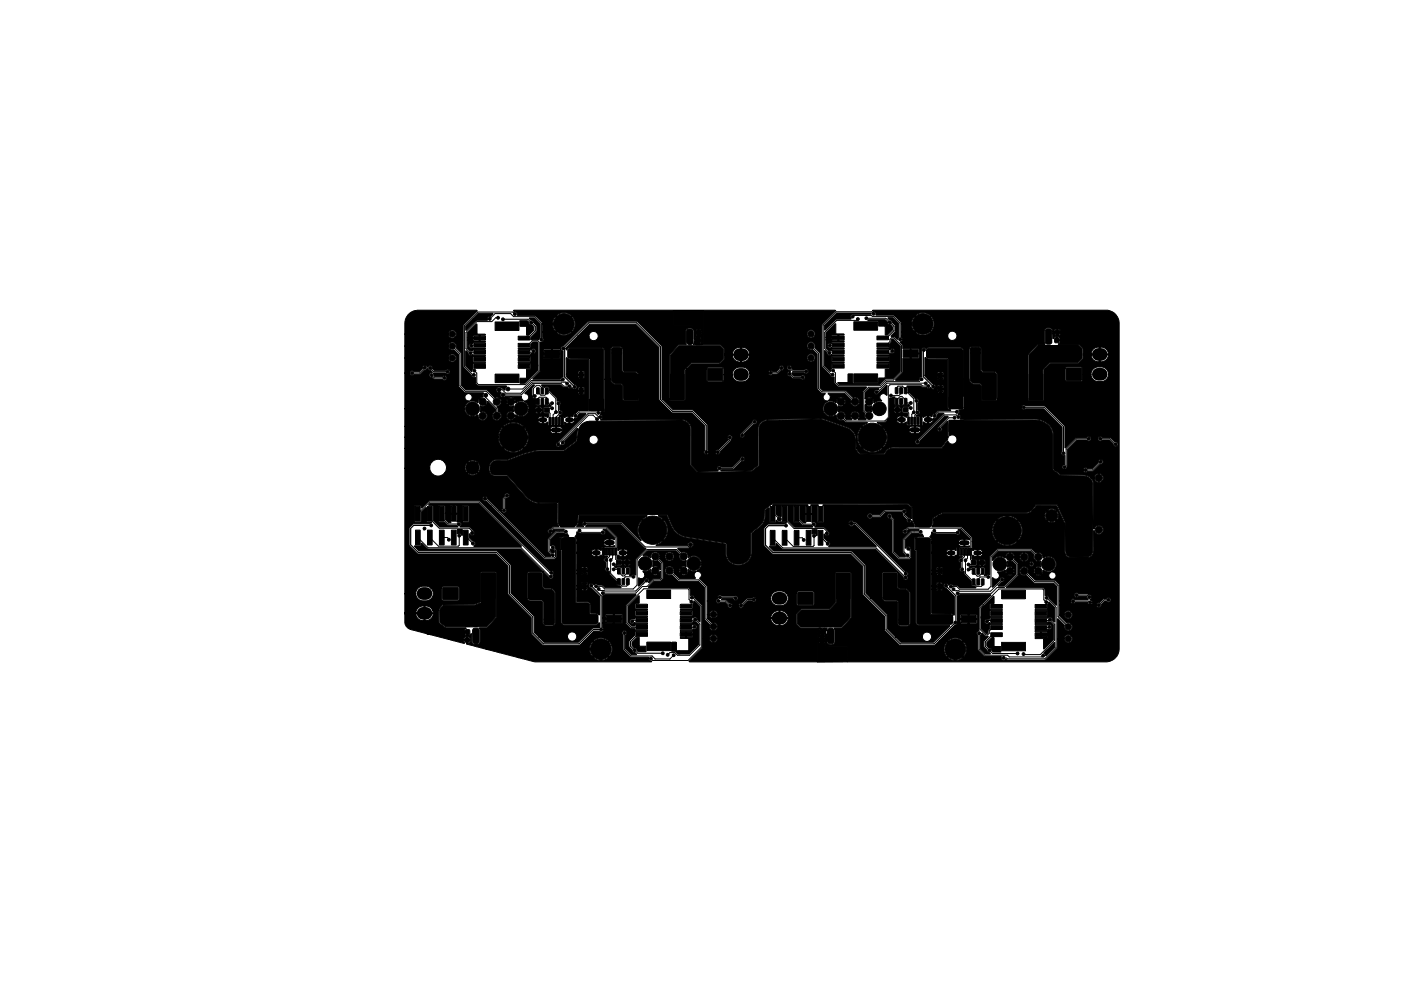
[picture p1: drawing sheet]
<svg xmlns="http://www.w3.org/2000/svg" width="297mm" height="210mm" viewBox="0 0 297 210" stroke-linecap="round" stroke-linejoin="round" font-family="sans-serif">
<g fill="#000" stroke="#000" stroke-width=".21">
<path d="M98.7 74.5l.2-.1 .4 .5a.5 .5 0 0 0 .5 .5l.4-.2 .3 .1 2.4 .1-.1 .2-2.4 .1-.1 1 .2 .1h2.3l.1 .3-2.5 .1-.1 1-.2 .6h-.2l-1.2-1.2zM100.5 77.3h2.4v.8h-2.4zM100.5 75.8h2.4v.8h-2.4zM100.5 74.3h2.4v.8h-2.4zM100.5 72.8h2.4v.8h-2.4zM100.5 71.3h2.4v.8h-2.4zM101 68.7l.1 .1v2.1l1.8 .1v.1h-1.1v1.2h1l.1 .2-2.4 .1-.4 .3a.51 .51 0 0 0-.7 .5 .58 .58 0 0 0 .9 .4h2.5l.1 .2-2.4 .1-.2 .3-.3 .1-.4-.1-.5-.6v-1.6l2.5 .1v-.5h-1.3v.4h-1.2v-.6h2.5v-.5h-1.2l-.1 .5h-1.2v-1zM86.7 66.6l.7-.5 1.2-.3h12.5v.2l-2.9 2.9v9l1.9 2 .7 .1v1.3l.5 .5 6.1 .1-.3 .9-.7-.5a.62 .62 0 0 0-.9-.2 .62 .62 0 0 0-.2 .8 .62 .62 0 0 0 .8 .3l.1 .1a.63 .63 0 0 0 0 .9 .63 .63 0 0 0 1-.1h3.3l.2 .6 .3 .3-.1 .1h-.9l-.6 .4-.3-.9-1.4 1.4a.98 .98 0 0 0 1.1 .1l.1 1.3-.7-.1-.7 .4a.96 .96 0 0 0 .6 1.5h5.9l.4 .5 .6 .1v-.6h-6.6l.6-.2h6v-.7l-.6 .1-.4 .6h-5l.4-1a1.67 1.67 0 0 0 2.6-.7h1.5l.4 .4h.7l.3-.4v-.2h-.6v.6h-.2v-.6h-.6v.2h-1.5l.1-.4h2.8v-.4l-.3-.2h-.3v.6h-.2v-.6l-.5 .1-.1 .5h-1.4a1.78 1.78 0 0 0-.9-1.8l.2-.1a.76 .76 0 0 0 .7-.4 .76 .76 0 0 0-.2-.8l-.6-.3v-.1l1.7-1.7h.3l-.5 .7v1.4l.2 .6 .5 .2 .1 1.3 .3 .2 .6-.2 .4 .2 .1-1 .1 1 .4-.2 .3 .2 .5-.1a.25 .25 0 0 1 .4-.1 .25 .25 0 0 1-.1 .4h-1l-.4 .3v.8l.4 .3h.6l.1 .6-.2 .3-.4-.2-.5-.1v1.5h.4l.5-.2 .2 .7h3.2l.1-.2 .1-.5 .6 .2h.8l.4-.1 .3-.3v-.2h-1v.6h-.2v-1.5h-.4l-.5 .3-.4-.2v1.9h-.2v-1.9l-.6-.1 .3-.2a.54 .54 0 0 0 .5-.7 .54 .54 0 0 0-.6-.4v-.9l.1-.2a.56 .56 0 0 0 0-.7 .56 .56 0 0 0-.7-.1v-.7l-.9-.9h5.4l.1 .2h1l.2-.1v-.6h-.6v.7h-.2v-.7h-.5v.5h-5.4l-.7-.7h7.4l-.1-.6-.5-.1v.7h-.2v-.7l-.5 .1v.6h-6.1l-.2-.7-.9 .1-.3-.2-.2-.3 3.9-.1 .6 .6h.9l.4 .3 .6-.3 .2 .3a.51 .51 0 0 0 .8-.2 .51 .51 0 0 0-.5-.7l-1.5-1.5h2.3l.1 .2h1l.2-.1v-.6h-.6v.7h-.2v-.7h-.5v.5h-2.3l-.3-.3v-.4h3.9v-.5l-.6-.2v.7h-.2v-.7l-.5 .1v.6h-2.6l.1-3.5 .8 .3 3.9 .1v10.8h-2.1l-.6 .6-.4 .1-.3 .6-.6-.1v.7h1v-.3l.5-.1 .2-.5 .5-.4 1.2 .1-6.3 6.4a.5 .5 0 0 0 .2 .5 .5 .5 0 0 0 .5 .1l.4-.4a.52 .52 0 0 0 .7-.2 .52 .52 0 0 0 0-.6l2.6-2.7h.2l-.4 2.6-2.6 2h-5.2l-1.1 .1-2.2 .6-3.4 1.3-2.9 .1-.7 .5-.3 1 .1 1.1 .4 .6 .7 .2h2.6l3.9 4.4 1.1 .9 1.6 .5h4v3.9l.4 1-1.3 .1-.4 .4-.5 .1-.2 .4a.5 .5 0 0 0 .6 .5l.4-.2 .1-.4 .3-.3h2.1l-.1 .2h-1.6l-1.7 1.7v2.8l.5 .6v.4l-1 .1-9.9-9.8h.5a.5 .5 0 0 0 .7 .5 .5 .5 0 0 0 .2-.8l-.1-2.1 .3-.3a.52 .52 0 0 0 .6-.5 .52 .52 0 0 0-.6-.5 .52 .52 0 0 0-.4 .7l-.4 .4v2.1l-.3 .5h-.5l-2.5-2.5a.51 .51 0 0 0-.6-.4 .51 .51 0 0 0-.4 .6 .51 .51 0 0 0 .8 .3l12.2 12.3h2.2l.5-.3v-1.6l-.3-.6a.5 .5 0 0 0-.3-.4 .5 .5 0 0 0-.5 .1l-.2-.1v-1.2l1.4-1.4h1.4l.4 .2 .4-.1 .2 .6-1 .1-.8 .1-.1 .2v2.4l.3 .3 .1 15.4 .6 .3h6.6l.4-.1 .4-.4 .1 .1v1l-1.5 .1-3 3h-7.2l-1.2-1.2h6.1a.98 .98 0 0 0 1.5 .8 .98 .98 0 0 0 .1-1.7 .98 .98 0 0 0-1.6 .7v.2h-6.1l-.9-.9v-3.4l-5-5v-6l-2.9-2.9h-16.6l-.9-1 1.3-.1 .2-.5 1.4 1.2h19.6l4.7 4.8-.1 .1-3-.1-.2 .2v5.3l.1 .4 .4 .3h2.5l.3 .3v4.4l.2 .4 .5 .2h1.4l.5-.5v-6.5l-.1-.3-.6-.6-1.4-.1-.5-.4v-3.1l1.2 1.1 .1 .3a.5 .5 0 0 0 .7 0 .5 .5 0 0 0 .1-.6v-.2a.54 .54 0 0 0 .1-.7 .54 .54 0 0 0-.7-.1l-14.9-14.9h-10.6l-1.7 1.6-.2-.6h-1.1l-.2 .1v3.4h1.3l.1-2 1-1 .1 .1v2.9l1.1 .2-.5 .2h-3.3l-.9 .8v3.9l1.8 1.7h16.5l2.6 2.6v6l4.9 4.9 .1 3.5 2.3 2.4h7.8l1.1-.9h1.9l1.6 1.6 1.6-1.6a2.35 2.35 0 0 0-3.2 0h-1.9l2-2.1 1.2 .1a.5 .5 0 0 0 .8-.3l-.1-1.6h.5l.2 .2h3.3l.1-.1v-.8h-1.7v.9h-.2v-.9h-1.6l-.1 .7h-.5v-.9h4.1v-.7l-.1-.2h-1.6v.9h-.2v-.9h-1.5l-.1 .1-.1 .8h-.5v-4.8l.5-.3h6.4l.1 .2-2.2 2.1v3.8l1.1 1.1 .9 .1 .2 .3 2.5 .1-.1 .2h-2.4l-.2 .7-1.2 1.3v1.2l.8 1.1 .7 .4v.2h-1.1l-1.2-1.3v-2.8l.2-.2a.5 .5 0 0 0-.1-.7 .5 .5 0 0 0-.7 .1 .5 .5 0 0 0 0 .7l.1 3.2 1.5 1.5h3.8l.2 .6 .6 .4h-24.8l-3.6-.9h16a2.37 2.37 0 0 0 3.2 0l-1.6-1.6-1.6 1.6h-16l-6.7-1.8h21.9l.2 .9 .4 .8 1.6-1.7h.3l1.7 1.7a2.35 2.35 0 0 0 0-3.3l-1.7 1.6h-.3l-1.6-1.6-.4 .7-.2 .9h-21.9l-4.2-1.1v-.1l.7-.1 .1-.5h-.6v.6h-.2v-.6h-.6l.2 .5-.1 .1-3.2-.8h4.5v-.4l-.3-.2h-.3v.6h-.2v-.6l-.4 .1-.2 .5h-3.1l-4.7-1.2h8l.2 .3h.3v-.6h-.5v.3h-8l-3.7-1-.6-.5-.3-.6-.1-2.2h2.4a1.56 1.56 0 0 0 1.7 1.5h.2a1.53 1.53 0 0 0 1.7-1.5h-1.7v1.5h-.2v-1.5h-4.1v-.2h6l-.1-.6h1.3l.1 2.6 .1 .3 1.3 .9h4.3l-.3 .4v.4h.7v.8h.4l.3-.4 .1 .1v1.5l.2 .5 .5 .2 .8-.1 .3-.6v-2.2l-.1-.6 1.6-.1 1.9-2.1v-9.5l-.3-.2h-2.8l-.2 .2-.1 6.2-1.2 .5-6.6 .1-1 1.1h-1.3l-.8-.7-.8-.1v1.4h-.2v-1.4a1.56 1.56 0 0 0-1.7 1.4h-2.4v-4h2.4a1.56 1.56 0 0 0 1.4 1.5l1.2-.1 .8-.6 .3-.9-.2-.7-.4-.4h2.4v2.3l.2 .3 3.1 .1 .4-.4v-2.4l-.4-.3h-3l-.3 .4h-2.4l-.6-.4h-1.2l-1 .5-.3 1.1h-2.4v-26.7h5.3a1.78 1.78 0 0 0 1.2 1.6 1.78 1.78 0 0 0 1.9-.5h4.9a1.57 1.57 0 0 0 2.1 0l-1-1-1.1 1h-4.9l.3-.5 .2-.7h3.9l.4 1.1 1-1.1h.3l1.1 1.1a1.57 1.57 0 0 0 0-2.1l-1.1 1h-.3l-1-1-.4 1h-3.9l-.1-.6-.4-.6h4.9l1.1 1.1 1-1.1a1.57 1.57 0 0 0-2.1 0h-4.9l-.9-.5a1.77 1.77 0 0 0-2.2 1.8h-5.3v-4.2h20.9a3.2 3.2 0 0 0 4.3 0l-2.2-2.2-2.1 2.2h-20.9v-2.4h19.8a3.1 3.1 0 0 0 .9 2.3l2.2-2.2h.3l2.2 2.2a3.2 3.2 0 0 0 .5-3.7h4.9l.2 .4 .3 .2 1.4 .1 .5-.2 .2-.5h-1.2v.7h-.2v-.7h-6.1l-.1-.2h7.6l-.2-.4-.4-.2h-.6v.6h-.2v-.6l-.8 .1-.4 .5h-5l-.4-.5-2.2 2.2h-.3l-2.2-2.2a3.1 3.1 0 0 0-.9 2.1h-19.8v-2.2h20.9l2.1 2.1 2.2-2.1a3.2 3.2 0 0 0-4.3 0h-20.9v-3.8h12.7a1.72 1.72 0 0 0 1 1.5 1.72 1.72 0 0 0 1.8-.2l.1 .3a.96 .96 0 0 0 1.2 .8 .96 .96 0 0 0 .5-1.4l-.6-.4h-.7v-1.2l.7 .1 .4-.2-1.3-1.4-.3 .8-.9-.3h-.7v-.1a.77 .77 0 0 0 .4-.8 .77 .77 0 0 0-.5-.6l-.2-.1a.76 .76 0 0 0-.8 .6l.2 .7 .7 .3a1.94 1.94 0 0 0-1 1.6h-12.7v-7.6h1.1a.5 .5 0 0 0 .5 .6l.4-.3h1.3l.8-.8 .4-.1 .3-.3 1 .7-.1 .2a.5 .5 0 0 0-.4 .7l.9 .6h1.8l.1 .1a.51 .51 0 0 0 .7-.1 .51 .51 0 0 0-.1-.7 .51 .51 0 0 0-.7 .2h-1.6l-.3-.7 2.5-.1 .2 .1a.51 .51 0 0 0 .7-.1 .51 .51 0 0 0-.1-.7 .51 .51 0 0 0-.8 .2h-2.3l-.4-.4a.55 .55 0 0 0-.4-.6 .55 .55 0 0 0-.7 .3 .55 .55 0 0 0-.6-.4 .55 .55 0 0 0-.4 .7l-.8 .7h-1a.5 .5 0 0 0-.9 0l-.1 .2h-1v-3.1h9.2a.86 .86 0 0 0 1.3 .7 .86 .86 0 0 0 .1-1.4 .86 .86 0 0 0-1.3 .5l-.1 .2h-9.2v-2.6h9.2a.94 .94 0 0 0 1.3 .8l.9 1 .1 6.8 1.3 1.3h3.9l-.1 .9-.7 .3 1.4 1.3 .2-.6h.2l1.5 1.6 .1 .5-.4 .2a.96 .96 0 0 0 0 1.5 .96 .96 0 0 0 1.5-.3 .96 .96 0 0 0-.5-1.4l-.3-1.1a1.05 1.05 0 0 0 .9-.9l1.1-.1 .2 .6 .6-.6-.6-.6-.2 .6h-1.1l-.4-.7h1.8l.6 .6 .6-.6a.93 .93 0 0 0-1.2 0l-2.8-.2-1.7-1.6h-4.4l-1-1v-6.7l-1.1-1.2a.88 .88 0 0 0-.6-1.2 .88 .88 0 0 0-1.1 .8h-9.2v-2.5h9.2l.1 .2a.86 .86 0 0 0 1.3 .5 .86 .86 0 0 0-.1-1.5 .86 .86 0 0 0-1.3 .8h-9.2l.1-2.9zM98.8 69.1l2.6-2.6h3.1v.1l-.7 .6a.5 .5 0 0 0-.5 .6v.2h-2.3l-2.2 2.1zM105 79.4h5v1.8h-5zM105 68.3h5v1.8h-5zM109.9 77.3h2.4v.8h-2.4z"/>
<path d="M109.9 75.8h2.4v.8h-2.4zM109.9 74.3h2.4v.8h-2.4zM109.9 72.8h2.4v.8h-2.4zM109.9 71.3h2.4v.8h-2.4zM110.2 68.1h1.6l.5 .7 .4 .1 .4 .5v.7l-1 1h-.5v-1.9h-1.3zM112.2 67.5h1.1l1.2 1.2v2.9l-.3 .5h-1.7v-.5l1.3-1.3v-1.1l-.9-1.2-.4-.1zM109.9 73.9l2.5-.1 .1-.8 .5-.4 .9-.1 .2 .2v5.8l-2.9 2.8h-.9l-.1-1 1.4-.1v-1.8l.9-.1v-1l-.2-.2h-2.3l-.1-.2 2.5-.1 .1-1-.2-.2h-2.3l-.1-.2 2.4-.1 .3-.3h.6a.51 .51 0 0 0 .4-.8 .51 .51 0 0 0-.9 0l-2.7-.1zM115.4 74.2h3.2v1.6h-3.2zM120.4 74.2h3.2v1.6h-3.2zM122.8 78.9h.9v1.2h-.9zM126.1 78.9h.9v1.2h-.9zM120.6 74.1l.3-.2h6.6l.5 .3v12.4l-.2 .5h-2.4l-.3-.4v-10.7h-4.4l-.3-.5z"/>
<path d="M129.8 73.9l.3-.2h1.3l.4 .3 .1 4.6 .4 .4h2.4l.4 .3 .1 5-.3 .4h-2.4l-.2-.4v-2.5l-.6-.5h-1.5l-.5-.6-.1-6.4zM145.9 70.1h.8v.9h-.8zM146 73.5h.8v.9h-.8zM146 71.8h.8v.9h-.8zM145.7 70l.9-.2 .3 .4 .1 2.4-.4 .5h-.7l-.3-.4v-2.4zM147.2 72.6l.5 .5h-.7zM147.7 70.1h.8v.9h-.8zM147.6 73.5h.8v.9h-.8zM147.6 71.8h.8v.9h-.8zM142.7 66l6.4-.1v6.7l-.4 .5h-1.1l-.3-.4 .1-.1 .2 .3h.7l.3-.2v-.2h-.3v.4h-.5v-.4l-.5 .1v-.6h1.3v-.3l-.3-.2v.5h-.5v-.5l-.5 .5v-1.2h.2l.4 .4h.6l.3-.4h-.4v.4h-.5v-.4h-.6v-.5h1.5l-.2-.3-.2-.1v.4h-.5v-.4l-.4 .4h-.2v-.8l-.5-.4h-4.1zM143.9 73.4l8.7-.1 .8 .8v1.9l-1 1h-5.9l-1.4 1.5-.1 6.2-2.8 .1-.1-.1v-9.3zM174.8 74.4h.2l.3 .5a.5 .5 0 0 0 .6 .5l.4-.2 .2 .1h2.4v.3h-2.4l-.2 1 .2 .2h2.4l.1 .3h-2.5l-.2 1.1-.2 .6h-.1l-1.2-1.2z"/>
<path d="M176.5 77.3h2.5v.8h-2.5zM176.5 75.8h2.5v.8h-2.5zM176.5 74.3h2.5v.8h-2.5zM176.5 72.8h2.5v.8h-2.5zM176.5 71.3h2.5v.8h-2.5zM108.9 65.8h68.2v.2l-2.8 2.9v8.9l1.9 2.1 .6 .1 .1 1.3 .8 .8h6l-.8 1.1v3.9l.5 .6a1.21 1.21 0 0 0 .2 1.2l-.1 .2-1.5-.1 .2-1-.1-.3-.4-.4h-.8l-.4 .4a1.14 1.14 0 0 0 .1 1.3h-1.1l-.4-.3 .1-.7-.2-.5-.5-.2-.8 .1 .1-1.3a.96 .96 0 0 0 1.1-.1l-.8-.8h.3l.6 .6a.95 .95 0 0 0 0-1.2l-.6 .6h-.3l-.6-.6-.2 .8-.7-.3-1-.1 .4-.5h1.7l.6 .6 .6-.6a.93 .93 0 0 0-1.2 0h-1.7l-.1-.6-.3-.4 3.4-.1 1.4 1.3-.1 .3a.97 .97 0 0 0 .9 1.2 .97 .97 0 0 0 1-1v-.3l-.4-.5-.3-.1h-.7l-1.5-1.5h-4.9l-.5-.5v-7.4l-1.1-1.1a.89 .89 0 0 0-.7-1.3 .89 .89 0 0 0-1 1 .89 .89 0 0 0 1.3 .7l.9 .9v7.4l.8 .9h.8l.1 .2a.79 .79 0 0 0-.5 .7 .79 .79 0 0 0 .5 .7l.5 .2a1.71 1.71 0 0 0-.8 2.4 1.71 1.71 0 0 0 2.6 .4v.3a.98 .98 0 0 0 1.4 .8l.7 .5h4.5v.2l-1.1 .7 2.2 2.1 2.1-2.1-1-.7v-.2h1.6l.4-.5h2l.3 .6 .7 .1v-.7h-3l.3-.2h2.7v-.6l-.6 .1-.4 .5h-1.7l.2-.3v-1.4h.9l.4 .4h.9l.2-.4v-.1h-.6v.5h-.2v-.5h-.7v.1h-.9v-.4h2.4v-.3l-.4-.2h-.2v.5h-.2v-.5l-.5 .1-.2 .4h-.9v-2.4l1.1-.2-.1 1.5 .2 .3 .8-.1 .3 .1 .1-.9 .2 .9 .3-.1 .7 .1 .2-.1a.24 .24 0 0 1 .4 0 .24 .24 0 0 1-.1 .4h-1.1l-.3 .2v.9l.3 .2h.7l.1 .7-.2 .3-.4-.3h-.5v1.5h.4l.4-.3 .3 .7h3.1l.2-.1 .1-.6 .5 .3h.9l.4-.2 .2-.3 .1-.2h-1v.7h-.2v-1.5h-.5l-.4 .3-.4-.3v1.9h-.2v-1.9l-1-.1 .8-.4a.6 .6 0 0 0-.4-.9v-1.4l.2-.3a.51 .51 0 0 0-.2-.5 .51 .51 0 0 0-.5-.1l-1.5-1.5h6.2l.2 .2h.9l.2-.1v-.6h-.6v.7h-.2v-.7h-.5v.5h-6.2l-.3-1.2h2.8l.4 .2 .9 .1 .4 .2 .6-.2 .3 .3 .2 .1 .3-.2h1.9v-.5l-.6-.2v.7h-.2v-.7h-.4l-.1 .7h-.5a.53 .53 0 0 0-.5-.9l-1.2-1.2h2.2l.2 .2h.9l.2-.1v-.6h-.6v.7h-.2v-.7h-.5v.5h-2.2l-.5-.5v-.2h4v-.5l-.6-.2v.7h-.2v-.7l-.5 .1v.6h-2.7v-3.7l.9 .3h3.9v10l.1 .6 .6 .3h-2.7l-.6 .6-.5 .1-.2 .6-.7-.1v.6h.9l.1-.2 .6-.1 .1-.5 .5-.4h1l-5.5 5.5a.51 .51 0 0 0-.6 .7l.2 .2a.51 .51 0 0 0 .5 .1 .51 .51 0 0 0 .3-.5l5.3-5.4h.7v.2l-2 1.9-.3 .7a.51 .51 0 0 0 .8 .4 .51 .51 0 0 0 .1-.8l1.2-1.3h.2l.1 3.3-.2 .6-1.3 1.6h-10.5l-.8 .3-.9 1h-4.5a1.18 1.18 0 0 1-1.3-1.1h1.2a3.2 3.2 0 0 0 4.3 0l-2.2-2.2-2.1 2.2h-1.2v-1.9h.2l.2 .9 .6 .9 2.2-2.2h.3l2.2 2.2a3.1 3.1 0 0 0 .5-3.7h4.9l.2 .4 .3 .2h1.4l.4-.1 .3-.5h-1.2v.6h-.2v-.6h-6.1l-.2-.2h7.7l-.2-.4-.5-.3h-.5v.7h-.2v-.7l-.8 .1-.4 .6h-5.1l-.3-.5-2.2 2.2h-.3l-2.2-2.2a3.6 3.6 0 0 0-.9 2.5l-.7-1.4-.8-.8-5.6-2-1.1-.1-10.9 .2-1.2 .6-.4 .4-.3 .7v8l-1.4 1.1-6.5 .1 .2-.3h2.5l1.8-1.7a.52 .52 0 0 0 .6-.6 .52 .52 0 0 0-.6-.4 .52 .52 0 0 0-.4 .6l-1.7 1.6h-2.3a.5 .5 0 0 0-.6-.2 .5 .5 0 0 0-.3 .6l.3 .3-.1 .2h-4.2l-1.4-1.4-.1-8-.4-.8-.7-.6-.9-.2-17.1 .2-.1-.2a.58 .58 0 0 0 .5-.5 .58 .58 0 0 0-.5-.6l.1-.5 .7-.1 .1-.2v-6.6h1.2l.1 .4 .6 .6 1.5 .1 .4 .3 .1 2.9 .1 .2h3l.1-.1 .1-.6v-4.9l-.6-.5-2.4-.1-.3-.2v-4.4l-.1-.3-.4-.3h-1.6l-.6 .5v6.4h-1.2v-6.1l-.3-.6-.4-.1h-6.6l-.4 .1-.4 .5-.2-.3 2.5-2.7h2.5a.98 .98 0 0 0 1.4 .9 .98 .98 0 0 0 .1-1.7 .98 .98 0 0 0-1.5 .7v.1h-2.5l2.6-2.5h9.8l4.9 4.9v11.2l2.7 2.7h4.3l2.7 2.7v5.2l-.2 .3a.51 .51 0 0 0 .6 .6l.4-.2v-.3h1.5a.5 .5 0 0 0 .5 .5l.3-.1 .2-.5 2.2-2.2 .3-.8-.2-.4h1.9a.52 .52 0 0 0 .7 .5 .52 .52 0 0 0 .2-.8l2-2.1h.2a.51 .51 0 0 0 .5-.6 .51 .51 0 0 0-.6-.4 .51 .51 0 0 0-.4 .6l-2.4 2.4-.2 .4h-1.9a.56 .56 0 0 0-.7 .2 .56 .56 0 0 0 .1 .7l-2.1 2.1-.4 .1-.2 .4h-1.5l-.1-.4-.1-5.5-3.1-3-4.2-.1-2.3-2.2h1.5l.2 .3 3.1-.1 .1-6.3 .2-.3h4.3v2.3l.3 .4h3l.4-.4v-1.1h1.8v.3a1.57 1.57 0 0 0 1.4 1.2h1l.7-.3 .5-.8v-.8h4a.5 .5 0 0 0 .6 .5l.4-.2h.9l.8-.8 .5-.1 .1-.5h.6a.5 .5 0 0 0 .6 .5l.2 .3-.6 .2-.1 .4 .2 .3 .5 .1 .5 .5h1.6l.2 .2a.5 .5 0 0 0 .8-.3 .5 .5 0 0 0-.6-.6l-.4 .2h-1.4l-.3-.3-.1-.4h2.6l.1 .1a.5 .5 0 0 0 .7-.1 .5 .5 0 0 0 0-.7 .5 .5 0 0 0-.8 .1h-2.2l-.4-.3a.52 .52 0 0 0-.5-.7 .52 .52 0 0 0-.6 .5l-.6-.1a.53 .53 0 0 0-.6-.3 .53 .53 0 0 0-.4 .6l-.6 .6h-.8a.5 .5 0 0 0-.8 0l-.1 .3h-4a1.55 1.55 0 0 0-1.3-1.2h-1l-.7 .3-.5 .6-.1 .7h-1.8v-1.2l-.4-.4h-3l-.3 .4h-4.3l1.1-1.1h5.9l1-1 .1-.8h1.7a1.56 1.56 0 0 0 1.7 1.4h.2a1.53 1.53 0 0 0 1.6-.9h12.3v.2a.86 .86 0 0 0 1.4 .5 .86 .86 0 0 0-.2-1.5 .86 .86 0 0 0-1.2 .8h-12.3l.2-.6h-1.8v1.5h-.2v-1.5l-3.4 .1v-.3h5.4a1.54 1.54 0 0 0-1.5-1.4h-.3v1.4h-.2v-1.4a1.54 1.54 0 0 0-1.7 1.4h-1.7l-.1-1.1-.9-.8-4.2-.1h.3l.4-.5v-1.8h22a.86 .86 0 0 0 1.2 .8 .86 .86 0 0 0 .2-1.4 .86 .86 0 0 0-1.4 .5v.1h-22v-4.9l-6.4 .1v3.1h4.1l.5 .4v2.4l-.3-2-.5-.3-.8 .1-.3 .6v2.3l.1 .5-1.7 .1-1.9 2.1v9.4l-1.5-.1-.1-11.2-5.2-5.2h-10.5l-5.1 5.2-.4 .2-.3 .5h-1.7v.8h1.7l.1-.7 .5 .3v5.4l-.6 .6-5.8-.1 1.6-1.7v-2.8h.6l.2 .1h3.2l.2-.1v-.8l-1.7 .1v.8h-.2v-.9h-1.7v.8h-.6v-1h2.3v-.9l-1.6 .1-.1 .8h-.6v-2.3a.56 .56 0 0 0 .6-.2 .56 .56 0 0 0 0-.6l-.1-.2v-1.1h2.8a2.37 2.37 0 0 0 3.3 0l-1.7-1.6-1.6 1.6h-2.8v-1.8h2l.2 .9 .5 .8 1.6-1.7h.3l1.6 1.7a2.38 2.38 0 0 0 0-3.3l-1.6 1.6h-.3l-1.6-1.6-.5 .7-.2 .9h-2l-.1-.3-1.4-1.4h4.3l1.6 1.6 1.7-1.6a2.35 2.35 0 0 0-3.3 0l-8.3-.2a.61 .61 0 0 0-.6-.8zM175.1 70.6l2-1.9 .1 .1v2l1.8 .1-.1 .2h-1v1.2h1v.3h-2.4l-.3 .3a.51 .51 0 0 0-.8 .4 .58 .58 0 0 0 1 .4l2.5 .1 .1 .2-2.5 .1-.2 .3h-.6l-.6-.6v-1.7l2.5 .2 .1-.5h-1.4v.3h-1.2v-.5h2.5l.1-.5h-1.2l-.2 .1v.4h-1.2zM181 68.3h5.1v1.8h-5.1zM181 79.3h5.1v1.8h-5.1zM174.8 69.1l2.7-2.7h7.1l.1 .1-.1 .2h-4a.6 .6 0 0 0-.1 1h-3.2l-2.4 2.3zM185.9 77.3h2.5v.8h-2.5zM185.9 75.8h2.5v.8h-2.5z"/>
<path d="M185.9 74.3h2.5v.8h-2.5zM185.9 72.8h2.5v.8h-2.5zM185.9 71.3h2.5v.8h-2.5zM184.1 67.9l3.6-.1 .4 .5 .2 .5 .5 .1 .4 .4v.7l-1 1.1h-.5v-1.9h-1.4l-.1-1.1h-2.1zM188.3 67.4h1.1l1.2 1.3v2.8l-.3 .5-.7-.6-.7-.1 .9-1 .1-1.1-.9-1.2-.4-.1zM177.6 81.2l2.2-.1v-1.7l.9-.1 .3 2h5.2l.1-1.1h1.4v-1.8l.8-.2 .1-.9-.2-.2h-2.4l-.1-.3h2.6l.1-1-.2-.2h-2.4l-.1-.3h2.5l.2-.3h.4a.56 .56 0 0 0 .7-.5 .5 .5 0 0 0-.7-.5l-.4 .3-.2-.2h-2.4l-.1-.2 2.6-.1 .1-.9 .3-.3 .1-.5 .2-.2h.2l1.5 1.5v5.4l-1.6 1.6h-1.6l-1.3 1.2h-8.5zM191.5 74.2h3.2v1.6h-3.2zM196.5 74.2h3.2v1.6h-3.2zM199 79.1h.9v1.2h-.9zM202.3 79.1h.9v1.2h-.9zM196.6 74l.4-.1h6.6l.4 .2 .1 12.1-.3 .5h-2.2l-.5-.4v-10.3l-4.4-.1-.2-.4v-1.1zM205.8 73.8l.4-.1h1.2l.5 .3v4.6l.4 .4h2.4l.5 .3v4.9l-.2 .5h-2.4l-.3-.4v-2.5l-.5-.5-1.5-.1-.6-.5v-6.5z"/>
<path d="M221.9 70.1h.9v.8h-.9zM222 73.4h.8v1h-.8zM222 71.7h.8v1h-.8zM221.8 69.9l.8-.1 .4 .3v2.4l-.3 .5h-.7l-.4-.3v-2.4zM223.8 70.1h.8v.8h-.8zM223.7 73.4h.8v1h-.8zM223.7 71.7h.8v1h-.8zM220 73.3h8.6l.8 .8v1.9l-.9 1h-5.9l-1.5 1.5v6.2l-2.8 .1-.1-.2v-9.2zM122.8 109.4h14.3l.1 .1-1 .7 2.2 2.1 2.2-2.1-1-.8h1.7l1.4 2.9 .9 1 .8 .4 1.1 .4 8.4 1.3v2.4l.3 .8 .9 .9 1.2 .4 1-.1 .6-.2 .8-.6 .4-.5 .3-1.3v-4l1.9-1.6 .5-.6 .4-1.1 .1-1.7 .7-.5 .1 .1 .1 3h1.2l.1-.4h.2a.6 .6 0 0 0 .8 .3l.3 .1h.8l.1 .2-.5 .2h-3.3l-.9 .7v4l1.9 1.7h16.5l2.5 2.6v5.9l4.6 4.6 .1 3 3.1 3.2h7.4l1-.9h1.8l1.6 1.6 1.7-1.6a2.38 2.38 0 0 0-3.3 0h-1.8l3.4-3.4 .4-.1 .1-.3h.6l.2 .1h3.2l.2-.1v-.8h-1.7v.9h-.2v-.9h-1.7v.8h-.6v-1h4.2v-.7l-.2-.2h-1.5v.9h-.2v-.9l-1.6 .1-.1 .8h-.6v-4.7l.5-.3h6.6l-2.6 2.7v4.6l.1 .3-.3 .2a.5 .5 0 0 0 0 .7v3.2l1.3 1.3 3.6 .1 .1 .1a.5 .5 0 0 0 .5 .7l.4-.2 .4 .1h8l2.6-2.5v-2h1.4a.86 .86 0 0 0 1.3 .8 .86 .86 0 0 0 .1-1.5 .86 .86 0 0 0-1.4 .5v.2h-1.4v-4.2h.2l1.3 1.3a.88 .88 0 0 0 .5 1.3 .88 .88 0 0 0 1.1-.9 .88 .88 0 0 0-1.1-.8l-1.5-1.5v-.3h.9a.86 .86 0 0 0 1.3 .8 .86 .86 0 0 0 .1-1.4 .86 .86 0 0 0-1.4 .5v.1h-.9v-2h7.8l.2 .4a.5 .5 0 0 0 .8-.3v-.3l.7-.7 .5 .1a.51 .51 0 0 0 .7-.1 .51 .51 0 0 0-.1-.7 .51 .51 0 0 0-.7 .2h-.6l-.9 .8-.4 .2-.2 .4h-7.8v-.9h2.3l.1 .3 .3 .2 .6-.2h2.5l.3 .4a.5 .5 0 0 0 .8-.2 .5 .5 0 0 0-.4-.7l-.1-.1 .2-.1a.53 .53 0 0 0 .1-.7 .53 .53 0 0 0-.6-.3l-.3-.1h-1.8a.51 .51 0 0 0-.9 0 .5 .5 0 0 0 .1 .6 .5 .5 0 0 0 .6 .1l.2-.2h1.6l.4 .7-2.8 .1a.5 .5 0 0 0-.8 0l-.1 .2h-2.3l-.1-3.5-1-.9h-4.1l-1.2-1.2h1.2a.93 .93 0 0 0 1.2 0l-.6-.6-.6 .6h-1.2l-.2-.3v-.4h1.1l.2 .6 .6-.6-.6-.6-.2 .6h-1.1l-.3-.7-.5-.3-.5 .1-.5 .3a.96 .96 0 0 0 .6 1.5h.7l1.7 1.6 4.1 .1 .6 .6v4h-.2l-1.4-1.4a.56 .56 0 0 0-.6-.7h-.2v-1.2l-.4-.4-7.8-.1 2.5-2.6v-2.4h2.3v.2a.5 .5 0 0 0 .7 .3 .51 .51 0 0 0 .1-.9 .51 .51 0 0 0-.8 .4h-2.3l-.9-.9 .1-.5h1.1l.3 .7a.96 .96 0 0 0 1.1 .1 .96 .96 0 0 0 .5-1l-.3-.5-.7-.3-.6 .3-.3 .7h-1.1l-.2-.6-.2-.2-.6-.2-.3 .1a.96 .96 0 0 0-.6 1l-.1 .1-.6-.3-.8-.1-.7 .3-.5 .6-.1-.1v-.6l1.3-1.3h6.8l.8 .8a1.01 1.01 0 0 0 .1 1.1l.5 .3h.8v1.2l-.7-.1-.5 .2 1.4 1.4 .2-.8 .7 .3 1 .1a.79 .79 0 0 0-.4 .8 .79 .79 0 0 0 .6 .7 .77 .77 0 0 0 .9-.8l-.2-.5-.7-.3v-.1a1.66 1.66 0 0 0 .8-2.1 1.66 1.66 0 0 0-2-1l-.7 .3-.1-.6-.3-.4-.6-.2-.4 .1-1.1-.9h-7.1l-1.6 1.6-.1 3.9-1.1 .2 .1-1.5-.2-.3-.7 .2-.4-.2-.1 1-.1-1-.4 .2-.3-.2-.5 .1a.28 .28 0 0 1-.4 .2 .28 .28 0 0 1-.2-.4l.3-.2 1 .1 .4-.4h.2l.4 .4h.8l.3-.4v-.2h-.6v.6h-.2v-.6h-.6l-.1 .2h-.2v-.4h1.7l-.2-.5-.4-.1v.6h-.2v-.6l-.4 .1-.3 .5h-.2l-.2-.5-.9-.2-.1-.5 .2-.3 .6 .3h1l.4-.3 .2-.4h-1v.7h-.2v-.9h1.1v-.1l-.3-.4-.3-.1h-.3v.6h-.2v-.6l-1 .2-.1-1.9h5.3a3.2 3.2 0 0 0 4.3 0l-2.2-2.2-2.1 2.2h-5.3v-.9l-1.4-1.5h5.6l.2 1.1 .7 1.2 2.2-2.2h.3l2.2 2.2a3.2 3.2 0 0 0 .1-4.3h6a1.45 1.45 0 0 0 1.9 0l-.9-.9-1 .9h-6l-.1-.1-2.2 2.2h-.3l-2.2-2.2a3 3 0 0 0-.9 2.1h-5.6l-.9-.7h-6.1l-.1-.1 .2-.6 .1-.8h13.5l2.1 2.1 2.2-2.1a3.2 3.2 0 0 0-4.3 0h-13.5v-.3l1.2-.6h22.4l.4 1 .9-1h.3l1 1a1.46 1.46 0 0 0 0-2l-1 1h-.3l-.9-1-.4 1h-22.4l.8-.5h17.6l.8-.2 .7-.4h3l1 1 .9-1a1.43 1.43 0 0 0-1.9 0h-3l.7-1 4.4 .1 1.6 3.6 .1 6 .2 .7 .4 .5 4.2 .1 .8-.4 .5-.9v-4.3l.1-.1a.96 .96 0 0 0 1.6 .5 .96 .96 0 0 0-.2-1.6 .96 .96 0 0 0-1.4 .7h-.1l-.1-9.6-.2-.7-.3-.5h.7v.2a.96 .96 0 0 0 1.6 .5 .96 .96 0 0 0-.2-1.6 .96 .96 0 0 0-1.4 .9h-.7l-.7-.4-.7-.2-5-.1-1.3-1h6.1l.1 .4 .4 .1 .4-.2h1.1l1.5-1.5h.2a.52 .52 0 0 0 .5-.6 .52 .52 0 0 0-.7-.4 .52 .52 0 0 0-.3 .6l-1.3 1.3h-1a.5 .5 0 0 0-.8 .1l-.1 .2h-6.1l-.2-.2-.1-8-.8-1.3-1.5-1-1.6-.3-15.1 .1h-.7v-.2a.56 .56 0 0 0-.5-.9l.3-.4-.1-.5 1-.1 .1-.5h12.1a.5 .5 0 0 0 .6 .5l.4-.2h3.8l3.9 3.9v5.1l-.2 .2a.5 .5 0 0 0 .4 .8h.4v1.8l-.4 .2a.5 .5 0 0 0-.1 .8h.1a.52 .52 0 0 0 .6 .1 .52 .52 0 0 0 .2-.6l.1-3.6 2.1-2.1h2l.1 .2a.51 .51 0 0 0 .6 0 .51 .51 0 0 0 .2-.4h1.5a.51 .51 0 0 0 .7 .4l.3-.2 1.4 .1 .8 .7 .2 .6a.52 .52 0 0 0 .8-.4 .52 .52 0 0 0-.6-.6l-1-.9h-1.7a.51 .51 0 0 0-.8 0l-.1 .3h-1.5v-.2a.55 .55 0 0 0-.9-.1h-2.2l-2.4 2.3-.1-4.8-4.2-4.2h-4.1a.5 .5 0 0 0-.8 0l-.1 .3h-12.1l-.1-6h1.2l.1 .4 .6 .6 1.5 .1 .4 .3v3l.1 .1 3 .1 .2-.4h6.6l.2 .4h2.8l.3-.1v-.3v-6l.3-.4h4.2v2.4l.4 .4h3l.3-.4v-1.1h1.8a1.55 1.55 0 0 0 1.5 1.5l.9-.1 .7-.3 .6-.8v-.7a1.57 1.57 0 0 0-1.4-1.2h-1l-.7 .3-.4 .5-.2 .8h-1.8v-1.3l-.4-.3h-2.9l-.4 .3h-4.2l1.1-1h5.8l1.1-1v-.9h1.7a1.56 1.56 0 0 0 1.8 1.5l.2-.1a1.52 1.52 0 0 0 1.7-1.4h-1.7v1.4h-.2v-1.4h-3.5v-.2h5.4a1.54 1.54 0 0 0-1.4-1.4h-.3v1.4h-.2v-1.4a1.54 1.54 0 0 0-1.8 1.4h-1.7v-1.1l-.9-.9h-4.3l.3-.4v-.4h-.6l-.1-.2h.7v-.4l-.5-.2v.6h-.2v-.6h-.4l-.4 .3v-1h.3l.3 .4h.7l.3-.2 .1-.4h-.6v.6h-.2v-.6h-.6v.2h-.3v-.4h1.7l-.2-.4-.4-.2v.6h-.2v-.6h-.3l-.3 .3v.3h-.3l-.1-.4-.2-.3-1.1-.1-.4 .7v2.2l.2 .6-1.7 .1-1.9 2.1v9.3h-6.6v-5.3l-.5-.5h-2.5l-.2-.3-.1-4.3-.3-.6-1.8-.1-.5 .5v6.4h-1.2v-6l-.3-.6-.4-.1h-6.6l-.7 .3a.51 .51 0 0 0-.6-.2 .51 .51 0 0 0-.3 .6v5.5l-.4 .3-.1 .4-5 .1v-.2l1.5-1.5v-3h3.3l.2-.2v-.7h-1.7v.9h-.2v-1.1h1.9l-.1-.8-1.6-.1v.9h-.2v-.9h-1.6v-.8l-.5-.6a.59 .59 0 0 0 .4-.4 .59 .59 0 0 0-.2-.6v-.3h9.8l.2 .6 .3 .2a.98 .98 0 0 0 1.2-.1 .98 .98 0 0 0 .2-1.2l-.4-.4a.98 .98 0 0 0-1.5 .9h-9.8v-.8h2.9a2.37 2.37 0 0 0 3.3 0l-1.7-1.6-1.6 1.6h-2.9v-1.8h2.1l.2 .9 .5 .8 1.6-1.7h.3l1.6 1.7a2.35 2.35 0 0 0 0-3.3l-1.6 1.6h-.3l-1.6-1.6-.5 .7-.2 .9h-2.1l-.1-.4-1.3-1.3h4.3l1.6 1.6 1.7-1.6a2.35 2.35 0 0 0-3.3 0l-8.2-.1-.1-.2a.51 .51 0 0 0-.5-.6l-.2-.1v-.2h49.5a2.79 2.79 0 0 1 2.8 2.8l-.1 69.7a2.78 2.78 0 0 1-2.7 2.1h-54.9v-.9h21.3a2.37 2.37 0 0 0 3.3 0l-1.7-1.6-1.6 1.6h-21.3v-1.8h20.5l.2 .9 .5 .8 1.6-1.7h.3l1.6 1.7a2.38 2.38 0 0 0 0-3.3l-1.6 1.6h-.3l-1.6-1.6-.5 .7-.2 .9h-20.5v-.5h-4l-.5-.3v-2.4l.3 2 .5 .3 .8-.1 .3-.6v-2.3l-.1-.5 1.7-.1 1.9-2.2v-9.3l-.1-.2-.3-.1h-2.8l-.2 .1v6.3l-1.3 1.4h-5.9l-1.1 1v2.1l.8 .9 4.4 .1h-.3l-.4 .4v6.7h-27.2v-.1l2.8-2.9 .1-1.9h1.4a.86 .86 0 0 0 1.2 .7 .86 .86 0 0 0 .2-1.4 .86 .86 0 0 0-1.4 .5v.2h-1.4l-.1-7-1.7-1.8a.53 .53 0 0 0-.7-.4h-.1l-.1-1.3-.4-.4h-8.4l1.2-1.3h1.4l.5-.5v-3.3l-.8-1 .1-.5h1.1l.1 .6 .4 .3a.96 .96 0 0 0 1.4-.8l-.3-.7-.7-.3-.6 .3-.3 .6h-1.1l-.3-.6-.7-.3-.6 .3-.4 .9-.6-.3-1-.2 1-1h6l.8 .8-.1 .6 .2 .5 .5 .3 .8-.1-.1 1.3a.96 .96 0 0 0-1.1 .1l1.4 1.4 .3-.9 .6 .3 1 .2a.99 .99 0 0 0-.2 1.4h-3.3l-1-.9h1.2a.93 .93 0 0 0 1.2 0l-.6-.6-.6 .6h-1.2l-.2-.3v-.4h1.1l.2 .6 .6-.6-.6-.6-.2 .6h-1.1l-.3-.7-.5-.3-.5 .1-.5 .3a.96 .96 0 0 0 .1 1.2 .96 .96 0 0 0 1.1 .3l1.5 1.3h4.2l1.3 1.3 .1 6.8 1 1.1a.89 .89 0 0 0 .7 1.3 .89 .89 0 0 0 1-1 .89 .89 0 0 0-1.2-.7l-.9-.8h13.4a1.56 1.56 0 0 0 1.8 1.4h.2a1.52 1.52 0 0 0 1.7-1.5h-1.7v1.5h-.2v-1.5l-15.2 .1v-.9h.4v.2a.86 .86 0 0 0 1.4 .4h15.3a1.51 1.51 0 0 0-1.4-1.4h-.3v1.4h-.2v-1.4a1.56 1.56 0 0 0-1.8 1.4h-11.6a.86 .86 0 0 0-.2-1.4 .86 .86 0 0 0-1.2 .8h-.4v-2.9h1.8a.5 .5 0 0 0 .5 .5l.4-.2h1l.6 .5v.3a.5 .5 0 0 0 .7 .4l.3-.5h1.3l.2 .4a.51 .51 0 0 0 .5 .1 .51 .51 0 0 0 .3-.5l.9-1 1 .1a.5 .5 0 0 0 .8-.2v-.4h3.1a1.56 1.56 0 0 0 1.5 1.5l1.2-.1 .7-.6 .3-.9-.2-.7-.3-.4h2.3v2.3l.3 .3h3.2l.2-.3v-2.5l-.4-.2h-2.9l-.4 .4h-2.3l-.6-.4h-1.3l-.9 .5-.3 .6-.1 .5h-3.1a.55 .55 0 0 0-1-.1h-1l-1 1.1-.5 .1-.2 .4h-1.3a.53 .53 0 0 0-.6-.5l-.8-.7-.8-.1-.1-.1 2.4-.1 .2 .3a.51 .51 0 0 0 .9-.3 .51 .51 0 0 0-.7-.5l-2.8-.1a.5 .5 0 0 0-.8 .1l-.1 .5-.3 .5h-1.8l-.1-3.1-1.6-1.7a.78 .78 0 0 0-.1-1.4l-.4-.2a1.82 1.82 0 0 0 1-1.5l-.1-.2a1.72 1.72 0 0 0-2.8-1.1l-.3-.9-.5-.3-.6 .1-.8-.8 .1-.1h2.1l.3-.1a.63 .63 0 0 0 .8-.4 .63 .63 0 0 0-.5-.8 .63 .63 0 0 0-.7 .7l-.1 .1h-6.6v-.2l.9-.4 .6-.4-2.3-2.3h.2l2.2 2.2a3.1 3.1 0 0 0 0-4.4l-2.2 2.2h-.2l-2.2-2.2a3.3 3.3 0 0 0-.2 4.3l-.1 .1-3.9-3.9h-7.5l-.5-.2-.4 .4 .2 .7h-1.4l.3-.7zM113.8 84.6h.5l-.1 1.3-.4-.1zM113.8 82.3l.5 .1-.1 1.2-.4-.1zM113.7 86.6h1v.8h-1z"/>
<path d="M114.7 84.6h.6l-.1 1.3-.5-.1zM114.7 82.3l.6 .1-.1 1.2-.5-.1zM115.7 84.6h.5l-.1 1.3-.4-.1zM115.7 82.3l.5 .1-.1 1.2-.4-.1zM116.4 88.6h.4v1.5h-.4zM115.5 86.6h.9v.8h-.9zM117 88.6h.5v1.5h-.5zM117.7 88.6h.4v1.5h-.4zM118.3 88.6h.5v1.5h-.5zM119 88.6h.4v1.5h-.4zM122.8 82.3h.9v1.2h-.9zM126.1 82.3h.9v1.2h-.9z"/>
<path d="M125 89.6h3v2.4h-3zM125 84.7h3v2.4h-3zM132.3 79.4h2.9v5.4h-2.9zM142.2 79.4h2.9v5.4h-2.9zM150 78.2h3.2v2.5h-3.2zM104.4 98.1l.6-.3 2.6-.1 3.5-1.3 2.5-.7h6l2.7-2.1 .1-.3h2.5v.3a.98 .98 0 0 0 1.6 .4 .98 .98 0 0 0-.3-1.6 .98 .98 0 0 0-1.3 .9h-2.5l.1-1.4a2.54 2.54 0 0 1 1.6-2.3l.9-.2 19.5-.2a1.79 1.79 0 0 1 1.8 1.8v7.7l1.5 1.6 11.6-.3 1.5-1.2v-7.8a1.97 1.97 0 0 1 2.1-1.8l10.9-.2 1 .2 4.6 1.6a2.81 2.81 0 0 1 1.9 2.6v1.9l.8 1.1h5.3l.9-1 .7-.3h10.6l1.2-1.6 .1 .2a.99 .99 0 0 0 1.4 .4 .99 .99 0 0 0 .3-1.4 .99 .99 0 0 0-1.4-.2l-.1-2.5 .2-.6 .3-.2 17.7-.1a4.1 4.1 0 0 1 2.5 .8l.2 .2a2.76 2.76 0 0 1 1 2.2v7.3l1.7 1.3 4.8 .1a1.76 1.76 0 0 1 2 1.6l.1 14.1a1.22 1.22 0 0 1-1.1 1.4h-3.8a.97 .97 0 0 1-.8-1.1l-.1-6.1-1.7-3.8h-4.6l-.9 1.2-1.2 .4h-17.7l-2.1 1.2-.1 1.2-.4 .7h-2.3a2.07 2.07 0 0 1-1.4-2v-2.2l-1-.7-28.7-.1-1.7 1.4-.1 1.2a2.88 2.88 0 0 1-1.1 2.3l-1.7 1.3v4.5a2.59 2.59 0 0 1-2.4 2.2 2.59 2.59 0 0 1-2.7-2v-2.5l-8.5-1.3a4 4 0 0 1-3.1-2.4l-1-2.4h-18.9l-.1 1.6a1.21 1.21 0 0 1-.8 1h-2.7l-.5-.4-.2-.6 .1-4.1h-3.8a4 4 0 0 1-3-1.3l-4-4.5h-2.7a1.42 1.42 0 0 1-.9-2.2zM184.2 82.5h2.2l-.3 .3-.3-.1-.4 .3a.5 .5 0 0 0 .1 .6 .5 .5 0 0 0 .5 .1l2-1.9 .1 2-.7-.3a.76 .76 0 0 0-.9 .6v.4l.4 .6h-.7l-.9 .3-.3-.8-1.3 1.4a.98 .98 0 0 0 1.1 .1v1.3h-1l-.4-.4v-1.1l.7-.7-.7-.7h.3l.6 .6 .6-.6a.9 .9 0 0 0-1.2 0h-.3v-1.2zM189.8 84.5l.6 .1-.1 1.2-.5-.1zM189.8 82.3h.6l-.1 1.2h-.5zM189.8 86.5h.9v.9h-.9zM190.8 84.5l.5 .1v1.2l-.5-.1zM190.8 82.3h.5v1.2h-.5z"/>
<path d="M191.7 84.5l.6 .1-.1 1.2-.5-.1zM191.7 82.3h.6l-.1 1.2h-.5zM192.4 88.5h.5v1.5h-.5zM191.5 86.5h1v.9h-1zM193.1 88.5h.4v1.5h-.4zM193.7 88.5h.5v1.5h-.5zM194.4 88.5h.4v1.5h-.4zM195 88.5h.5v1.5h-.5zM199 81.9h.9v1.2h-.9zM202.3 81.9h.9v1.2h-.9zM201.2 89.2h3v2.4h-3zM201.2 84.3h3v2.4h-3z"/>
<path d="M208.3 79.4h2.9v5.4h-2.9zM218.2 79.4h2.9v5.4h-2.9zM226.1 78.1h3.1v2.6h-3.1zM88.1 107.4h1v3.2h-1zM88.1 112.5h1v3.1h-1zM90.6 107.4h1v3.2h-1zM90.6 112.5h1v3.1h-1zM93.2 107.4h1v3.2h-1zM93.2 112.5h1v3.1h-1zM95.7 107.4h1v3.2h-1zM95.7 112.5h1v3.1h-1zM96.9 112.4h1.1v1.1l-.1 .1a.59 .59 0 0 0-.7-.4h-.3z"/>
<path d="M98.2 107.4h1v3.2h-1zM98.2 112.5h1v3.1h-1zM90.9 107.1l.3-.3h10.3l9 9-.1 .1h-9.9l.2-.3a.52 .52 0 0 0-.5-.8l-.7-.8v-.7l.3 .2a.5 .5 0 0 0 .7-.1 .5 .5 0 0 0-.1-.7l-.8-.9h-2v-.2a.51 .51 0 0 0 .1-.7 .51 .51 0 0 0-.7-.1l-.1-.2h1.1l.2 .2 1.2-.1v-3.4l-1.2-.1-.1 .1-.1 3.3h-1.1v-1.5h-1.4v1.8h-.4l-.7-.7v-1.3h2.5v-1.6l-.6-.1v1.7h-.2v-1.7l-.6 .2v1.5h-1.1l-.1-1.6h-1.3v3.4l1.3 .1 .6 .6h1.9l.3 .3-3.8 .1-1.5-1.4v-3.1l-.8-.1zM116.7 116.5l.8 .3v.5h-.4l-.4-.4zM118.8 109.3h3v2.4h-3zM118.8 114.2h3v2.4h-3zM119.3 114.2l.3-.2h2l.5 .4v13.5h2.4l.4 .2 .1 .3v1.9h1.4l.3 .3v1.4l-.3 .4h-6.7l-.5-.3-.1-17.5zM127.7 116.3h.5v1.5h-.5zM122.3 112.9l.9 .3h4.1l.2 .1a.5 .5 0 0 0 .8-.2v-.3l-.4-.4 .1-.1h.5l1.8 1.8v.4l-1-.1v1.5l.9-.2 .1 .3-2.3 .1v1.9h.7l.1 .1-.6 .3-.2 .2a.5 .5 0 0 0 .4 .7v1.1a.54 .54 0 0 0 0 .7 .54 .54 0 0 0 .8 .1l.1 .7 1.4 1.4 .1 .8 .6 .2 .3 .4h-3.4l-.6-.5-.8-.1a.75 .75 0 0 0-1.1 0 .5 .5 0 0 0-.8-.2 .5 .5 0 0 0 .3 .8l1.8 1.8v4l-.7-.4h-1.1l-.1-1.8-.3-.5-2.6-.2v-2.6h1l.2 .2h.9l.2-.2v-.5h-.6v.7h-.2v-.7h-.5v.5h-1v-.7h2.3v-.6l-.2-.1h-.4v.7h-.2v-.7l-.5 .1v.6h-1v-2.6h1l.2 .2h.9l.2-.2v-.5h-.6v.7h-.2v-.7h-.5v.5h-1v-.7h2.3v-.6l-.2-.1h-.4v.7h-.2v-.7l-.5 .1v.6h-1v-3.6h3.1l.1 .4 .5 .2h1l.4-.3 .4 .3v-1.9l-.3 .1v.6l-.4-.2-.6-.1v1.5h-.2v-.6h-4v-.2h4v-.7l-.5 .1-.4 .6h-3.1v-2h5.7l.1 .4 .5 .3h.5v-.7h-6.8v-.2h6.8v-.6l-.7 .1-.4 .5h-5.7v-.6l-.4-.6 .3-.4zM128.4 116.3h.4v1.5h-.4zM129 116.3h.5v1.5h-.5zM129.7 116.3h.4v1.5h-.4z"/>
<path d="M130.8 118.9h.9v.9h-.9zM130.3 116.3h.5v1.5h-.5zM124.5 111.3h7.2l4.9 4.9 .3 .1v.2l-2.1 2.1-.1 3.4a.64 .64 0 0 0-.9 .1l-.3-.1 .1-.3v-1.1l-.1-.3h-.6l-.2 .1-.4-.1-.1 .9-.1-.9-.4 .1-.8-.1a.27 .27 0 0 1-.4 .2 .27 .27 0 0 1 .1-.5h1l.4-.4h.2l.4 .4 1-.1 .1-.5-.6 .1-.1 .5h-.2v-.6h-.6v.2h-.2v-.4h1.7l-.3-.5h-.3l-.1 .5h-.2v-.5h-.4l-.2 .5h-.2l-.3-.5h-.7l-.2-.2v-.5l.2-.3 .6 .3h1l.3-.1 .2-.5h-.9l-.1 .6h-.2v-.8h1.2l-.1-.3-.3-.3-.5-.1-.1 .7h-.2v-.7l-.9 .2-.1-2.8-2.2-2.1-4.5-.1zM132.5 118.9h.9v.9h-.9zM137.1 113.6l.2 .2-.9 .7zM138.4 118.9h1l.7 .7v1.3h-.2l-.2-.4-.6 .6 .6 .6 .2-.5 .2 .1v1.3l-.2 .2h-1.4l-.8 .8h-.2a.53 .53 0 0 0-.1-.8 .53 .53 0 0 0-.7 .1l-.1 .4-1.2 1-.1-1.6h.4a.76 .76 0 0 0 1-.5v-.4h1.6a.93 .93 0 0 0 1.2 0l-.6-.6-.6 .6h-1.6l-.4-.5 1-.2 .6-.3 .3 .9 1.3-1.4a.98 .98 0 0 0-1.1-.1zM163.3 107.5h1v3.1h-1zM163.3 112.5h1v3.2h-1zM165.9 107.5h1v3.1h-1zM165.9 112.5h1v3.2h-1zM168.4 107.5h1v3.1h-1zM168.4 112.5h1v3.2h-1z"/>
<path d="M170.9 107.5h1v3.1h-1zM170.9 112.5h1v3.2h-1zM163.8 107.1h7.4l.1 .2-.6 .1v1.5h1.4v-1.5l-.2-.3h1.6l-.2 .4v3.1l.2 .2 1.2-.1v-3.2l-.2-.3 .1-.1h17.8l.9 .6v2.3l-.7-.2-.6-.5v-.3a.54 .54 0 0 0 .1-.9 .54 .54 0 0 0-.9 .1h-3.6l-1.1 1h-1.5l-.1-.1a.61 .61 0 0 0-.9 0 .61 .61 0 0 0 .1 .9 .61 .61 0 0 0 .9-.2l1.7-.1 1.1-1h3.4l.3 .2v.5l.7 1a.5 .5 0 0 0 .6 .5l.6-.4 .4 .8v.5h-1.3l-.5 .4-.3 .1a.5 .5 0 0 0-.3 .7l.2 .1a.51 .51 0 0 0 .5 .1 .51 .51 0 0 0 .3-.5l.3-.4 2.2 .1-.2 .2h-1.5l-1.7 1.7-.1 2.8 .5 .6 .1 .4h-1.3l-1-1v-6.8l-.6-.7a.51 .51 0 0 0-.5-.6 .51 .51 0 0 0-.5 .5 .51 .51 0 0 0 .6 .5l.4 .4 .1 7 1.3 1.3h2.3l.4-.4v-1.7a.61 .61 0 0 0-.4-.6 .61 .61 0 0 0-.6 .1l-.1 .2-.2-.1v-1.6l1.5-1.5h1.3l.4 .2h.5l.2 .6h-1.1l-.7 .2-.2 .1v2.5l.4 .3 .1 15.3 .6 .4h6.4l.1 .1-3.5 3.5h-6.9l-1.1-1.2h5.7l.1 .4 .4 .5a.98 .98 0 0 0 1.4-.6 .98 .98 0 0 0-.9-1.3 .98 .98 0 0 0-1 1h-5.7l-1.7-1.7-.1-3-3.6-3.6h2.5l.2 .5 .4 .2 2.5 .1 .2 .3 .1 4.6 .6 .4 1.3-.1 .5-.1 .2-.6v-6.4l-.8-.8-1.4-.1-.5-.3v-2.9l-.1-.2-3.1 .1-.1 5.3h-2.5l-.9-1v-5.9l-3-3h-16.5l-1-1h1.3l.2-.6 1.4 1.2h19.6l5.9 5.9v.2a.5 .5 0 0 0 .6 .4 .5 .5 0 0 0 .3-.7l.1-.4a.5 .5 0 0 0-.5-.6l-10.5-10.4-.6-.3a.61 .61 0 0 0-.9 .1 .61 .61 0 0 0 .2 .8 .61 .61 0 0 0 .8-.1l.3-.1 4.5 4.6h-10.1a.57 .57 0 0 0 .3-.6 .57 .57 0 0 0-.6-.5l-.7-.7v-.8l.3 .2a.51 .51 0 0 0 .7-.1 .51 .51 0 0 0-.1-.7l-.8-.8h-2l.1-.3a.54 .54 0 0 0 0-.7 .54 .54 0 0 0-.8-.1v-1.7h-1.3v1.8h-.5l-.7-.7v-2.8l-.2-.1h-1.1l-.1 .2 .1 3.3h1.2l.6 .7h1.9l.3 .3h-3.9l-1.3-1.4-.1-3.1h-1.2l-.1 .1v2.1l-.2 .1h-.5l-.5-.5v-1.7l-.7-.1zM172.1 112.4h1.1l.1 1.1-.2 .1a.59 .59 0 0 0-.7-.4l-.3 .1zM173.5 107.5h1v3.1h-1zM173.5 112.5h1v3.2h-1zM194 109.4h3v2.4h-3zM194 114.3h3v2.4h-3zM194.5 114.3l.4-.2h1.9l.5 .4v15.8l4.4 .1 .3 .4v1.2l-.4 .4-6.7 .1-.5-.4v-17.5zM202.9 116.3h.5v1.5h-.5zM197.5 112.9l1 .4h4.1l.1 .1a.5 .5 0 0 0 .7 0 .5 .5 0 0 0 .1-.6l-.4-.4 .6-.1 1.8 1.9v.3l-.9-.1v1.5l.9-.1 .1 .2-2.3 .1v1.9l.8 .1-.2 .2-.5 .2a.5 .5 0 0 0 0 .7l.3 .2v.9l-.2 .3a.5 .5 0 0 0 .4 .7l.5-.1 .1 .7 1.4 1.4 .1 .9 .7 .1 .2 .4h-3.3l-.6-.5h-.9a.75 .75 0 0 0-1.1-.1 .5 .5 0 0 0-.6-.3 .5 .5 0 0 0-.3 .6l2.2 2.2v3.9l-.8-.3-4-.1v-5l2.2 .1 .1-.6-.5-.1v.7h-.2v-.7h-.6v.6h-1v-.8h2.3v-.5l-.1-.1-.4-.1v.7h-.2v-.7l-.4 .1-.2 .6h-1v-2.5l2.2 .1 .1-.6-.5-.1v.7h-.2v-.7h-.6v.6h-1v-.8h2.3v-.5l-.1-.1-.4-.1v.7h-.2v-.7l-.4 .1-.2 .6h-1v-3.6h3.1l.2 .4 .4 .3h1l.4-.3 .5 .2v-1.9l-.3 .1-.1 .6-.4-.2h-.5v1.5h-.2v-.7h-4.1v-.2h4.1v-.6h-.6l-.4 .6h-3.1v-1.9h5.7l.2 .4 .4 .2h.6v-.6h-6.9v-.2h6.9v-.7l-.8 .1-.4 .6h-5.7v-.7l-.4-.5 .4-.5zM203.6 116.3h.4v1.5h-.4z"/>
<path d="M204.2 116.3h.5v1.5h-.5zM204.9 116.3h.4v1.5h-.4zM206 119h.9v.8h-.9zM205.5 116.3h.5v1.5h-.5zM207.7 119h.9v.8h-.9zM213.6 119h1l.8 .8v1.9l-2.6 2.6-1.2 .1v-.2l.8-.7a.51 .51 0 0 0 .6-.6 .51 .51 0 0 0-.7-.4 .51 .51 0 0 0-.3 .6l-1.6 1.5v-2l.5 .2a.76 .76 0 0 0 1-.5v-.4h1.6a.93 .93 0 0 0 1.2 0l-.6-.6-.6 .6h-1.6l-.4-.5 1-.1 .6-.4 .3 .9 .6-.6h.3l.6 .6a.95 .95 0 0 0 0-1.2l-.6 .6h-.3l.7-.8a.98 .98 0 0 0-1.1-.1zM93.9 124.6h3.2v2.6h-3.2zM98.7 131.9h.8v1h-.8zM98.7 133.6h.8v1h-.8zM98.6 135.4h.8v.8h-.8zM100.3 133.4l.9-.1 .4 .3v2.4l-.4 .5h-.7l-.3-.3v-2.4zM100.4 131.9h.8v1h-.8z"/>
<path d="M100.4 133.6h.8v1h-.8zM100.4 135.4h.9v.8h-.9zM93.9 128.5l6.7-.1 1.5-.6v-6.2h2.9v9.3l-1.8 2.1h-8.7l-1.2-1-.1-2.6zM102.1 121.5h2.9v5.4h-2.9zM112.1 121.7l.4-.2 2.2 .1 .2 .4v2.5l.5 .5h1.4l.7 .6v6.5l-.2 .4-1.6 .1-.4-.4v-4.5l-.4-.4h-2.4l-.4-.3-.1-4.9zM112 121.5h2.9v5.4h-2.9zM120.2 123.8h.9v1.2h-.9zM120.2 120.5h.9v1.2h-.9zM123.5 123.8h.9v1.2h-.9zM123.5 120.5h.9v1.2h-.9zM123.5 130.5h3.2v1.6h-3.2zM128.5 130.5h3.2v1.6h-3.2z"/>
<path d="M131 120.5l.5 .1-.1 1.2-.5-.1zM131 122.8h.5l-.1 1.3-.5-.1zM131.9 120.5l.6 .1-.1 1.2-.5-.1zM131.9 122.8h.6l-.1 1.3-.5-.1zM132.9 120.5l.5 .1-.1 1.2-.5-.1zM132.9 122.8h.5l-.1 1.3-.5-.1zM135.4 126.4l.1 .1v1.4l-.8 .2-.1 1 .2 .1h2.4l.1 .2-2.5 .1-.2 1.1 .2 .1h2.4l.1 .2-2.5 .1-.2 .3-.4 .1a.51 .51 0 0 0-.7 .6l.4 .3 .7-.3 .2 .2h2.4l.1 .3h-2.5l-.2 .3h-.6l-.9-.8 .1-3.4zM134 136.3l1-1.1h.4l.1 1.9 1.4 .1v1.1h-1.5l-.3-.3a.6 .6 0 0 0-.7-.6l-.4-.5zM134.8 128.2h2.5v.8h-2.5zM134.8 129.7h2.5v.8h-2.5zM134.8 131.2h2.5v.8h-2.5zM134.8 132.7h2.5v.8h-2.5z"/>
<path d="M134.8 134.2h2.5v.8h-2.5zM137.1 136.2h5.1v1.8h-5.1zM137.1 125.2h5.1v1.8h-5.1zM144.2 128.2h2.5v.8h-2.5zM144.2 129.7h2.5v.8h-2.5zM144.2 131.2h2.5v.8h-2.5zM144.2 132.7h2.5v.8h-2.5zM144.2 134.2h2.5v.8h-2.5zM144.3 132.2h2.4l.2-.3h.3h.3l.6 .6v4.2l-2.1 2.1h-2.2l-.6-.6h-.8l.1-2 .9 .1v1.8h2.6v-2.6h-1.7l-.1-.2 2.6-.1 .1-.5h-1.3v.5h-.2v-.7h1.5v-.4l-1.3-.1v.5h-.2v-.5h-1.1l-.1-.2 2.6-.1a.5 .5 0 0 1 .7-.3 .54 .54 0 0 0 .1-.8 .54 .54 0 0 0-.8 0l-2.5-.1zM144.3 129.2h2.5l.1-1.1 .2-.6h.2l1.1 1.2v3.2l-.5-.3a.54 .54 0 0 0-.3-.6 .54 .54 0 0 0-.7 .1l-.2-.1h-2.4v-.3h2.5l.1-1-.2-.2h-2.4zM169.2 125.7h3.1v2.5h-3.1zM174 132h.8v.9h-.8z"/>
<path d="M174 133.7h.8v.9h-.8zM173.8 135.4h.9v.9h-.9zM173.7 133.3h1l.4 .4v3.2l.5 .3h4v3.2l-6.3 .1v-4.4h.3l.4 .4h.6l.3-.4h-.4v.4h-.5v-.4h-.7v-.5h1.6l-.4-.4v.4h-.5v-.4l-.4 .4h-.3v-1.1h.4l.3 .3h.6l.4-.3-.4-.1v.4h-.5v-.4l-.8 .1v-.6h1.7l-.1-.3-.3-.1v.4h-.5v-.4l-.3 .1-.1 .3h-.4zM174.7 133.3h.6l-.1 .5zM175.6 133.5l.8-.2 .4 .4v2.4l-.3 .5-.7-.1-.3-.3-.1-2.4zM175.6 132h.8v.9h-.8zM175.6 133.7h.8v.9h-.8zM175.7 135.4h.8v.9h-.8zM177.3 121.7h3l-.1 9.3-1.8 2h-8.6l-.8-.7v-2l.9-.9h6l1.4-1.5zM177.3 121.6h2.9v5.4h-2.9zM187.4 121.7l.3-.1 2.2 .1 .2 .4v2.5l.6 .4 1.4 .1 .6 .6 .1 6.4-.3 .5h-1.6l-.4-.3v-4.6l-.4-.4h-2.4l-.4-.2-.1-5zM187.2 121.6h2.9v5.4h-2.9z"/>
<path d="M195.4 120.5h.9v1.2h-.9zM195.4 123.8h.9v1.2h-.9zM198.7 120.5h.9v1.2h-.9zM198.7 123.8h.9v1.2h-.9zM198.8 130.5h3.2v1.6h-3.2zM203.8 130.5h3.2v1.6h-3.2zM206.2 120.6h.5v1.2h-.5zM206.2 122.8l.5 .1v1.2l-.5-.1zM207.1 120.6h.6l-.1 1.2h-.5zM207.1 122.8l.6 .1-.1 1.2-.5-.1zM208.1 134.4l.7 .5 .7 .1-.9 1.2v1l.6 .7a.74 .74 0 0 0 .8 .7l-.1 .2-1-.1-1-1v-2.9zM208.1 120.6h.5v1.2h-.5z"/>
<path d="M208.1 122.8l.5 .1v1.2l-.5-.1zM208 129.1l2.6-2.6 .2 .1v1.4l-.9 .1v1l.1 .2h2.5l-.1 .3h-2.4l-.1 .1 .1 1 2.4 .1v.2l-2.4 .1-.2 .3-.9 .1a.5 .5 0 0 0 0 .8l.4 .1 .5-.3 .2 .2h2.4l.1 .2-2.5 .1-.1 .7-.4 .5v.5l-.5 .1-1-1.1zM209.3 136.3l1-1h.4l.1 1.9h1.4l-.1 1.1-1.5 .1-.3-.4a.53 .53 0 0 0-.6-.5l-.5-.5zM210.1 128.3h2.4v.8h-2.4zM210.1 129.8h2.4v.8h-2.4zM210.1 131.3h2.4v.8h-2.4zM210.1 132.8h2.4v.8h-2.4zM210.1 134.3h2.4v.8h-2.4zM212.4 136.3h5v1.8h-5zM212.4 125.2h5v1.8h-5zM219.5 128.3h2.4v.8h-2.4zM219.5 129.8h2.4v.8h-2.4z"/>
<path d="M219.5 131.3h2.4v.8h-2.4zM219.5 132.8h2.4v.8h-2.4zM219.5 134.3h2.4v.8h-2.4zM219.5 132.3h2.4l.2-.3 .3-.1 .4 .1 .5 .6v3.2l-2 1.9v-2.2h-1.7l-.1-.1 2.5-.2 .1-.4h-1.3v.4h-.2v-.7l1.5 .1v-.4l-1.3-.1v.4h-.2v-.4h-1l-.1-.2 2.4-.1 .3-.3h.4a.51 .51 0 0 0 .3-.7 .51 .51 0 0 0-.8-.2h-2.5zM219.5 129.3l2.5-.1 .1-1 .4-.4 1.2 1.2-.1 2.9-.5-.3a.58 .58 0 0 0-.3-.6 .58 .58 0 0 0-.7 .2l-2.6-.2 .1-.2 2.4-.1 .1-1-.2-.1h-2.3zM221.3 138.5l2.2-2.2 .1 .1v.9l-1.8 1.8z"/>
<circle cx="87.4" cy="79.1" r=".3"/>
<circle cx="90.1" cy="78" r=".3"/>
<circle cx="91.2" cy="78.1" r=".3"/>
<circle cx="91.5" cy="79.6" r=".3"/>
<circle cx="94.2" cy="66.6" r=".3"/>
<circle cx="94.9" cy="78.8" r=".3"/>
<circle cx="95.9" cy="73.4" r=".65"/>
<circle cx="95.9" cy="70.9" r=".65"/>
<circle cx="95.9" cy="76" r=".65"/>
<circle cx="97.8" cy="72.3" r=".3"/>
<circle cx="99.6" cy="71.7" r=".3"/>
<circle cx="99.8" cy="74.9" r=".3"/>
<circle cx="99.8" cy="77.2" r=".3"/>
<circle cx="99.9" cy="73.4" r=".3"/>
<circle cx="100.5" cy="79.5" r=".3"/>
<circle cx="100.5" cy="67.9" r=".3"/>
<circle cx="100.5" cy="69.9" r=".3"/>
<circle cx="100.6" cy="78.6" r=".3"/>
<circle cx="103.8" cy="67.7" r=".3"/>
<circle cx="105.6" cy="67.4" r=".3"/>
<circle cx="106.6" cy="67.7" r=".3"/>
<circle cx="109.2" cy="66.6" r=".3"/>
<circle cx="112.6" cy="69.2" r=".3"/>
<circle cx="112.6" cy="68.4" r=".3"/>
<circle cx="113.1" cy="74.5" r=".3"/>
<circle cx="113.3" cy="73.2" r=".3"/>
<circle cx="113.7" cy="77.5" r=".3"/>
<circle cx="113.9" cy="71.1" r=".3"/>
<circle cx="114.8" cy="72" r=".3"/>
<circle cx="116.1" cy="79.7" r=".3"/>
<circle cx="117.9" cy="68.7" r=".35"/>
<circle cx="118.4" cy="69.9" r=".35"/>
<circle cx="118.4" cy="67.6" r=".35"/>
<circle cx="119.4" cy="73.9" r=".3"/>
<circle cx="119.5" cy="67.1" r=".35"/>
<circle cx="119.5" cy="68.7" r="2.2"/>
<circle cx="119.5" cy="70.4" r=".35"/>
<circle cx="120.7" cy="69.9" r=".35"/>
<circle cx="120.7" cy="67.6" r=".35"/>
<circle cx="121" cy="78.7" r=".3"/>
<circle cx="121" cy="77.2" r=".3"/>
<circle cx="121.2" cy="68.7" r=".35"/>
<circle cx="126" cy="77.8" r=".3"/>
<circle cx="126.1" cy="77.1" r=".3"/>
<circle cx="126.7" cy="77.8" r=".3"/>
<circle cx="126.8" cy="77.1" r=".3"/>
<circle cx="127.3" cy="77.8" r=".3"/>
<circle cx="127.5" cy="77.1" r=".3"/>
<circle cx="127.5" cy="78.4" r=".3"/>
<circle cx="130.1" cy="74.9" r=".3"/>
<circle cx="130.1" cy="74.2" r=".3"/>
<circle cx="130.8" cy="74.9" r=".3"/>
<circle cx="130.8" cy="74.2" r=".3"/>
<circle cx="131.5" cy="74.9" r=".3"/>
<circle cx="131.5" cy="74.2" r=".3"/>
<circle cx="145.7" cy="67" r=".5"/>
<circle cx="145.7" cy="68.2" r=".5"/>
<circle cx="146.8" cy="67" r=".5"/>
<circle cx="146.8" cy="68.2" r=".5"/>
<circle cx="148" cy="67.1" r=".5"/>
<circle cx="148" cy="68.2" r=".5"/>
<circle cx="163.4" cy="79.1" r=".3"/>
<circle cx="165.7" cy="78.1" r=".3"/>
<circle cx="167.3" cy="78" r=".3"/>
<circle cx="167.4" cy="79.3" r=".3"/>
<circle cx="170.9" cy="78.8" r=".3"/>
<circle cx="172" cy="70.8" r=".65"/>
<circle cx="172" cy="75.9" r=".65"/>
<circle cx="172" cy="73.4" r=".65"/>
<circle cx="175.7" cy="71.7" r=".3"/>
<circle cx="175.8" cy="74.9" r=".3"/>
<circle cx="175.8" cy="77.2" r=".3"/>
<circle cx="176" cy="73.3" r=".3"/>
<circle cx="176.5" cy="79.5" r=".3"/>
<circle cx="176.5" cy="67.9" r=".3"/>
<circle cx="176.6" cy="69.9" r=".3"/>
<circle cx="176.6" cy="78.6" r=".3"/>
<circle cx="180.8" cy="67.2" r=".3"/>
<circle cx="181.9" cy="67.7" r=".3"/>
<circle cx="183.7" cy="67.5" r=".3"/>
<circle cx="185.2" cy="66.6" r=".3"/>
<circle cx="188.5" cy="79.8" r=".3"/>
<circle cx="188.6" cy="69.2" r=".3"/>
<circle cx="188.7" cy="68.4" r=".3"/>
<circle cx="189.2" cy="74.5" r=".3"/>
<circle cx="189.8" cy="77.5" r=".3"/>
<circle cx="189.9" cy="71.1" r=".3"/>
<circle cx="190.8" cy="72" r=".3"/>
<circle cx="192.2" cy="79.6" r=".3"/>
<circle cx="194" cy="68.7" r=".35"/>
<circle cx="194.5" cy="69.9" r=".35"/>
<circle cx="194.5" cy="67.6" r=".35"/>
<circle cx="195.6" cy="68.7" r="2.2"/>
<circle cx="195.6" cy="67.1" r=".35"/>
<circle cx="195.6" cy="70.4" r=".35"/>
<circle cx="195.9" cy="74.3" r=".3"/>
<circle cx="196.8" cy="69.9" r=".35"/>
<circle cx="196.8" cy="67.6" r=".35"/>
<circle cx="197.3" cy="68.7" r=".35"/>
<circle cx="197.6" cy="78.5" r=".3"/>
<circle cx="197.6" cy="77.1" r=".3"/>
<circle cx="197.6" cy="79.9" r=".3"/>
<circle cx="202.1" cy="77.8" r=".3"/>
<circle cx="202.2" cy="77.1" r=".3"/>
<circle cx="202.7" cy="77.8" r=".3"/>
<circle cx="202.9" cy="77.1" r=".3"/>
<circle cx="203.4" cy="77.8" r=".3"/>
<circle cx="203.4" cy="78.4" r=".3"/>
<circle cx="203.5" cy="77.1" r=".3"/>
<circle cx="206.1" cy="74.9" r=".3"/>
<circle cx="206.1" cy="74.2" r=".3"/>
<circle cx="206.9" cy="74.9" r=".3"/>
<circle cx="206.9" cy="74.2" r=".3"/>
<circle cx="207.6" cy="74.9" r=".3"/>
<circle cx="207.6" cy="74.2" r=".3"/>
<circle cx="222.6" cy="67" r=".5"/>
<circle cx="222.7" cy="68.2" r=".5"/>
<circle cx="223.8" cy="67" r=".5"/>
<circle cx="223.8" cy="68.2" r=".5"/>
<circle cx="224.9" cy="68.2" r=".5"/>
<circle cx="224.9" cy="67" r=".5"/>
<circle cx="91.3" cy="82.1" r=".3"/>
<circle cx="94.2" cy="80.2" r=".3"/>
<circle cx="100.2" cy="99.2" r="1.4"/>
<circle cx="100.2" cy="86.7" r="1.45"/>
<circle cx="102.3" cy="85.2" r=".76"/>
<circle cx="102.3" cy="88.2" r=".76"/>
<circle cx="103" cy="83.9" r=".4"/>
<circle cx="104.4" cy="82.9" r=".4"/>
<circle cx="105.3" cy="85.2" r=".76"/>
<circle cx="105.3" cy="88.2" r=".76"/>
<circle cx="105.7" cy="99.2" r="1.4"/>
<circle cx="105.8" cy="82.7" r=".4"/>
<circle cx="106.6" cy="92.8" r=".4"/>
<circle cx="106.7" cy="83.8" r=".4"/>
<circle cx="107.3" cy="91.2" r=".4"/>
<circle cx="107.3" cy="94.4" r=".4"/>
<circle cx="107.7" cy="82.5" r=".4"/>
<circle cx="108.3" cy="85.2" r=".76"/>
<circle cx="108.3" cy="88.2" r=".76"/>
<circle cx="108.8" cy="92.8" r="3"/>
<circle cx="108.8" cy="95" r=".4"/>
<circle cx="108.8" cy="90.5" r=".4"/>
<circle cx="110.4" cy="91.2" r=".4"/>
<circle cx="110.4" cy="94.4" r=".4"/>
<circle cx="110.5" cy="86.7" r="1.45"/>
<circle cx="111.1" cy="92.8" r=".4"/>
<circle cx="113.4" cy="84" r=".3"/>
<circle cx="117.1" cy="86.6" r=".3"/>
<circle cx="117.1" cy="85.5" r=".3"/>
<circle cx="117.9" cy="87.4" r=".3"/>
<circle cx="118.4" cy="94.3" r=".3"/>
<circle cx="118.4" cy="85.6" r=".3"/>
<circle cx="118.8" cy="87.5" r=".3"/>
<circle cx="119.3" cy="93.9" r=".3"/>
<circle cx="119.3" cy="80.5" r=".3"/>
<circle cx="119.5" cy="86.2" r=".3"/>
<circle cx="119.8" cy="83.8" r=".3"/>
<circle cx="120.2" cy="81.4" r=".3"/>
<circle cx="120.8" cy="82" r=".3"/>
<circle cx="120.9" cy="80.1" r=".3"/>
<circle cx="121.8" cy="82.1" r=".3"/>
<circle cx="121.8" cy="82.9" r=".3"/>
<circle cx="122" cy="88.2" r=".3"/>
<circle cx="126.6" cy="88.9" r=".3"/>
<circle cx="126.9" cy="87.6" r=".3"/>
<circle cx="127.2" cy="88.5" r=".3"/>
<circle cx="137.6" cy="81.5" r=".3"/>
<circle cx="149.6" cy="97.6" r=".3"/>
<circle cx="149.7" cy="95.9" r=".3"/>
<circle cx="152.2" cy="95.9" r=".3"/>
<circle cx="152.2" cy="93.3" r=".3"/>
<circle cx="152.2" cy="91.8" r=".3"/>
<circle cx="152.5" cy="99.4" r=".3"/>
<circle cx="154.4" cy="85.7" r=".5"/>
<circle cx="154.4" cy="83" r=".5"/>
<circle cx="154.4" cy="84.3" r=".5"/>
<circle cx="154.7" cy="92.8" r=".3"/>
<circle cx="154.9" cy="90.8" r=".3"/>
<circle cx="157.4" cy="92.4" r=".3"/>
<circle cx="157.4" cy="97.4" r=".3"/>
<circle cx="160" cy="89.5" r=".3"/>
<circle cx="165.3" cy="90.3" r=".3"/>
<circle cx="165.3" cy="89.6" r=".3"/>
<circle cx="166" cy="90.3" r=".3"/>
<circle cx="166" cy="89.6" r=".3"/>
<circle cx="166.7" cy="90.3" r=".3"/>
<circle cx="166.7" cy="89.6" r=".3"/>
<circle cx="167.4" cy="90.3" r=".3"/>
<circle cx="167.4" cy="89.6" r=".3"/>
<circle cx="167.6" cy="81.2" r=".3"/>
<circle cx="168.1" cy="90.3" r=".3"/>
<circle cx="168.1" cy="89.6" r=".3"/>
<circle cx="170.2" cy="80.1" r=".3"/>
<circle cx="176.1" cy="86.7" r="1.46"/>
<circle cx="178.3" cy="85.2" r=".76"/>
<circle cx="178.3" cy="88.2" r=".76"/>
<circle cx="181.3" cy="85.2" r=".76"/>
<circle cx="181.3" cy="88.2" r=".76"/>
<circle cx="182.7" cy="92.8" r=".4"/>
<circle cx="183.4" cy="91.2" r=".4"/>
<circle cx="183.4" cy="94.4" r=".4"/>
<circle cx="184.3" cy="85.2" r=".76"/>
<circle cx="184.3" cy="88.2" r=".76"/>
<circle cx="184.9" cy="92.8" r="3"/>
<circle cx="184.9" cy="95" r=".4"/>
<circle cx="184.9" cy="90.5" r=".4"/>
<circle cx="185.8" cy="83.2" r=".3"/>
<circle cx="186.4" cy="86.7" r="1.46"/>
<circle cx="186.5" cy="91.2" r=".4"/>
<circle cx="186.5" cy="94.4" r=".4"/>
<circle cx="187.2" cy="92.8" r=".4"/>
<circle cx="188.9" cy="83.9" r=".3"/>
<circle cx="193.1" cy="85.5" r=".3"/>
<circle cx="193.1" cy="86.6" r=".3"/>
<circle cx="193.7" cy="87.5" r=".3"/>
<circle cx="194.3" cy="85" r=".3"/>
<circle cx="194.5" cy="93.7" r=".3"/>
<circle cx="194.5" cy="87.5" r=".3"/>
<circle cx="195" cy="86" r=".3"/>
<circle cx="195.4" cy="80.5" r=".3"/>
<circle cx="195.4" cy="82.8" r=".3"/>
<circle cx="196.3" cy="81.3" r=".3"/>
<circle cx="196.8" cy="81.9" r=".3"/>
<circle cx="197.9" cy="82.1" r=".3"/>
<circle cx="198.1" cy="88.2" r=".3"/>
<circle cx="198.1" cy="85.3" r=".3"/>
<circle cx="199.2" cy="91.1" r=".3"/>
<circle cx="199.5" cy="84.4" r=".3"/>
<circle cx="202.4" cy="88.6" r=".3"/>
<circle cx="202.9" cy="87.4" r=".3"/>
<circle cx="203.2" cy="88.5" r=".3"/>
<circle cx="213.7" cy="81.5" r=".3"/>
<circle cx="217" cy="86.4" r=".3"/>
<circle cx="225.5" cy="96.2" r=".3"/>
<circle cx="225.7" cy="99.1" r=".3"/>
<circle cx="228.3" cy="98.1" r=".3"/>
<circle cx="230.2" cy="99.7" r=".3"/>
<circle cx="230.2" cy="85.2" r=".5"/>
<circle cx="230.2" cy="86.8" r=".5"/>
<circle cx="230.3" cy="83.6" r=".5"/>
<circle cx="230.8" cy="93.1" r=".3"/>
<circle cx="230.8" cy="94.5" r=".3"/>
<circle cx="230.8" cy="91.7" r=".3"/>
<circle cx="231.5" cy="83" r=".5"/>
<circle cx="233.1" cy="83" r=".5"/>
<circle cx="233.3" cy="93.1" r=".3"/>
<circle cx="233.4" cy="98" r=".3"/>
<circle cx="236.5" cy="94.3" r=".3"/>
<circle cx="90" cy="112.1" r=".3"/>
<circle cx="91.4" cy="111.5" r=".3"/>
<circle cx="94.8" cy="119.6" r=".5"/>
<circle cx="95.2" cy="114.5" r=".3"/>
<circle cx="96" cy="119.6" r=".5"/>
<circle cx="97.1" cy="119.6" r=".5"/>
<circle cx="97.3" cy="111.2" r=".3"/>
<circle cx="97.4" cy="113.7" r=".3"/>
<circle cx="97.5" cy="112.7" r=".3"/>
<circle cx="100.1" cy="113.1" r=".3"/>
<circle cx="100.3" cy="115.3" r=".3"/>
<circle cx="101" cy="109.4" r=".4"/>
<circle cx="102.8" cy="105.8" r=".3"/>
<circle cx="103.9" cy="107.6" r=".3"/>
<circle cx="106.9" cy="108.3" r=".3"/>
<circle cx="107.5" cy="105.1" r=".3"/>
<circle cx="109.5" cy="117.4" r=".3"/>
<circle cx="115" cy="112.1" r=".3"/>
<circle cx="116.6" cy="112.7" r=".3"/>
<circle cx="117.2" cy="116.1" r=".3"/>
<circle cx="117.2" cy="117.8" r=".3"/>
<circle cx="117.2" cy="116.9" r=".3"/>
<circle cx="120" cy="112.8" r=".3"/>
<circle cx="122.9" cy="112.6" r=".3"/>
<circle cx="123.3" cy="110.3" r=".3"/>
<circle cx="124" cy="111.1" r=".3"/>
<circle cx="127.8" cy="112.9" r=".3"/>
<circle cx="128.5" cy="118.8" r=".3"/>
<circle cx="129.5" cy="118.8" r=".3"/>
<circle cx="130.1" cy="119.7" r=".3"/>
<circle cx="136.1" cy="112.5" r=".4"/>
<circle cx="136.8" cy="119.6" r="1.45"/>
<circle cx="136.8" cy="110.9" r=".4"/>
<circle cx="136.8" cy="114.1" r=".4"/>
<circle cx="138.4" cy="112.5" r="3"/>
<circle cx="138.4" cy="114.7" r=".4"/>
<circle cx="138.4" cy="110.2" r=".4"/>
<circle cx="138.9" cy="118.1" r=".76"/>
<circle cx="140" cy="110.9" r=".4"/>
<circle cx="140" cy="114.1" r=".4"/>
<circle cx="140.6" cy="112.5" r=".4"/>
<circle cx="141.9" cy="118.1" r=".76"/>
<circle cx="144.9" cy="118.1" r=".76"/>
<circle cx="145.9" cy="114.8" r=".3"/>
<circle cx="146.4" cy="115.5" r=".4"/>
<circle cx="147.1" cy="119.6" r="1.46"/>
<circle cx="155" cy="117.4" r=".3"/>
<circle cx="155" cy="116.6" r=".3"/>
<circle cx="155.7" cy="117.4" r=".3"/>
<circle cx="155.7" cy="116.6" r=".3"/>
<circle cx="156.5" cy="117.4" r=".3"/>
<circle cx="156.5" cy="116.6" r=".3"/>
<circle cx="157.2" cy="117.4" r=".3"/>
<circle cx="157.2" cy="116.6" r=".3"/>
<circle cx="157.8" cy="117.4" r=".3"/>
<circle cx="157.8" cy="116.6" r=".3"/>
<circle cx="160.2" cy="112.9" r=".3"/>
<circle cx="165.1" cy="108.2" r=".3"/>
<circle cx="165.2" cy="110.1" r=".4"/>
<circle cx="166.6" cy="111.5" r=".3"/>
<circle cx="167.6" cy="119.4" r=".5"/>
<circle cx="168.8" cy="119.4" r=".5"/>
<circle cx="170.4" cy="114.6" r=".3"/>
<circle cx="172.5" cy="111.2" r=".3"/>
<circle cx="172.6" cy="113.7" r=".3"/>
<circle cx="172.7" cy="112.8" r=".3"/>
<circle cx="175.3" cy="113.1" r=".3"/>
<circle cx="175.5" cy="115.4" r=".3"/>
<circle cx="176.3" cy="107.6" r=".3"/>
<circle cx="180.5" cy="111" r=".4"/>
<circle cx="184.4" cy="109.5" r=".4"/>
<circle cx="184.7" cy="117.4" r=".3"/>
<circle cx="184.7" cy="110.6" r=".3"/>
<circle cx="188.6" cy="109.5" r=".3"/>
<circle cx="190.1" cy="109.2" r=".3"/>
<circle cx="190.7" cy="111.6" r=".3"/>
<circle cx="191.7" cy="108.5" r=".3"/>
<circle cx="191.9" cy="112.7" r=".3"/>
<circle cx="192.4" cy="117.8" r=".3"/>
<circle cx="192.6" cy="116.4" r=".3"/>
<circle cx="192.7" cy="110.4" r=".3"/>
<circle cx="195.2" cy="112.8" r=".3"/>
<circle cx="198.1" cy="112.6" r=".3"/>
<circle cx="198.9" cy="115" r=".3"/>
<circle cx="203" cy="118.1" r=".3"/>
<circle cx="203" cy="113" r=".3"/>
<circle cx="203.7" cy="118.8" r=".3"/>
<circle cx="204.7" cy="118.9" r=".3"/>
<circle cx="205.3" cy="119.8" r=".3"/>
<circle cx="211.3" cy="112.6" r=".4"/>
<circle cx="212" cy="114.2" r=".4"/>
<circle cx="212" cy="111" r=".4"/>
<circle cx="212" cy="119.7" r="1.45"/>
<circle cx="213.5" cy="112.6" r="3"/>
<circle cx="213.5" cy="110.3" r=".4"/>
<circle cx="213.5" cy="114.8" r=".4"/>
<circle cx="214.1" cy="118.2" r=".76"/>
<circle cx="215.1" cy="114.2" r=".4"/>
<circle cx="215.1" cy="111" r=".4"/>
<circle cx="215.8" cy="112.6" r=".4"/>
<circle cx="217.1" cy="118.2" r=".76"/>
<circle cx="218.7" cy="119.6" r=".3"/>
<circle cx="220.1" cy="118.2" r=".76"/>
<circle cx="222.3" cy="119.7" r="1.46"/>
<circle cx="223" cy="109.4" r="1.27"/>
<circle cx="223" cy="104.4" r="1.28"/>
<circle cx="227.2" cy="117.2" r=".3"/>
<circle cx="227.2" cy="116.4" r=".3"/>
<circle cx="227.9" cy="117.2" r=".3"/>
<circle cx="227.9" cy="116.4" r=".3"/>
<circle cx="228.6" cy="117.2" r=".3"/>
<circle cx="228.6" cy="116.4" r=".3"/>
<circle cx="229.3" cy="117.2" r=".3"/>
<circle cx="229.3" cy="116.4" r=".3"/>
<circle cx="230" cy="117.2" r=".3"/>
<circle cx="230" cy="116.4" r=".3"/>
<circle cx="233" cy="101.4" r=".75"/>
<circle cx="233" cy="112.4" r=".75"/>
<circle cx="109.5" cy="124.8" r=".3"/>
<circle cx="115.6" cy="132.1" r=".3"/>
<circle cx="115.6" cy="131.4" r=".3"/>
<circle cx="116.3" cy="132.1" r=".3"/>
<circle cx="116.3" cy="131.4" r=".3"/>
<circle cx="116.8" cy="122.3" r=".3"/>
<circle cx="116.9" cy="121.5" r=".3"/>
<circle cx="116.9" cy="120.7" r=".3"/>
<circle cx="117.1" cy="132.1" r=".3"/>
<circle cx="117.1" cy="131.4" r=".3"/>
<circle cx="119.7" cy="129.2" r=".3"/>
<circle cx="119.8" cy="127.9" r=".3"/>
<circle cx="119.8" cy="128.5" r=".3"/>
<circle cx="120.3" cy="129.2" r=".3"/>
<circle cx="120.5" cy="128.5" r=".3"/>
<circle cx="121" cy="129.2" r=".3"/>
<circle cx="121.1" cy="128.5" r=".3"/>
<circle cx="123.6" cy="128.4" r=".3"/>
<circle cx="123.6" cy="129.1" r=".3"/>
<circle cx="123.8" cy="126.1" r=".3"/>
<circle cx="123.8" cy="126.8" r=".3"/>
<circle cx="124.3" cy="128.7" r=".3"/>
<circle cx="124.4" cy="126.5" r=".3"/>
<circle cx="125.1" cy="121" r=".3"/>
<circle cx="125.1" cy="126.1" r=".3"/>
<circle cx="125.1" cy="126.8" r=".3"/>
<circle cx="125.3" cy="124.2" r=".3"/>
<circle cx="125.3" cy="123.4" r=".3"/>
<circle cx="125.7" cy="137.7" r=".35"/>
<circle cx="126.2" cy="138.9" r=".35"/>
<circle cx="126.2" cy="136.6" r=".35"/>
<circle cx="126.4" cy="124.4" r=".3"/>
<circle cx="126.9" cy="125" r=".3"/>
<circle cx="127.4" cy="137.7" r="2.2"/>
<circle cx="127.4" cy="136.1" r=".35"/>
<circle cx="127.4" cy="139.4" r=".35"/>
<circle cx="127.5" cy="133.6" r=".3"/>
<circle cx="127.6" cy="120.1" r=".3"/>
<circle cx="127.8" cy="123.5" r=".3"/>
<circle cx="127.8" cy="125.8" r=".3"/>
<circle cx="128.6" cy="138.9" r=".35"/>
<circle cx="128.6" cy="136.6" r=".35"/>
<circle cx="128.8" cy="120.7" r=".3"/>
<circle cx="129" cy="137.7" r=".35"/>
<circle cx="130.1" cy="120.8" r=".3"/>
<circle cx="131" cy="126.7" r=".3"/>
<circle cx="132.4" cy="134.3" r=".3"/>
<circle cx="133.3" cy="135.2" r=".3"/>
<circle cx="133.9" cy="129.1" r=".3"/>
<circle cx="134" cy="131.8" r=".3"/>
<circle cx="134.3" cy="122.4" r=".3"/>
<circle cx="134.5" cy="137.9" r=".3"/>
<circle cx="134.6" cy="137.1" r=".3"/>
<circle cx="137.1" cy="123.2" r=".3"/>
<circle cx="138" cy="139.7" r=".3"/>
<circle cx="138.9" cy="121.1" r=".76"/>
<circle cx="140.5" cy="138.6" r=".3"/>
<circle cx="141.6" cy="138.9" r=".3"/>
<circle cx="141.9" cy="121.1" r=".76"/>
<circle cx="142.8" cy="139" r=".3"/>
<circle cx="142.8" cy="137.7" r=".3"/>
<circle cx="144" cy="138.4" r=".3"/>
<circle cx="144.9" cy="121.1" r=".76"/>
<circle cx="146.6" cy="127.7" r=".3"/>
<circle cx="146.6" cy="136.5" r=".3"/>
<circle cx="146.7" cy="126.8" r=".3"/>
<circle cx="147.3" cy="133" r=".3"/>
<circle cx="147.4" cy="131.4" r=".3"/>
<circle cx="147.4" cy="128.2" r=".3"/>
<circle cx="147.5" cy="134.6" r=".3"/>
<circle cx="151.3" cy="130.4" r=".65"/>
<circle cx="151.3" cy="132.9" r=".65"/>
<circle cx="151.3" cy="135.5" r=".65"/>
<circle cx="152.3" cy="127.5" r=".3"/>
<circle cx="152.6" cy="126.7" r=".3"/>
<circle cx="154.8" cy="128.5" r=".3"/>
<circle cx="155.8" cy="124.2" r=".3"/>
<circle cx="156" cy="126.9" r=".3"/>
<circle cx="157.1" cy="128.5" r=".3"/>
<circle cx="159.8" cy="127.2" r=".3"/>
<circle cx="168.8" cy="121.7" r=".5"/>
<circle cx="168.8" cy="120.5" r=".5"/>
<circle cx="174.4" cy="138.2" r=".5"/>
<circle cx="174.4" cy="139.3" r=".5"/>
<circle cx="175.5" cy="138.2" r=".5"/>
<circle cx="175.5" cy="139.4" r=".5"/>
<circle cx="184.7" cy="124.9" r=".3"/>
<circle cx="190.9" cy="132.2" r=".3"/>
<circle cx="190.9" cy="131.5" r=".3"/>
<circle cx="191.6" cy="132.2" r=".3"/>
<circle cx="191.6" cy="131.5" r=".3"/>
<circle cx="192" cy="122.6" r=".3"/>
<circle cx="192" cy="121.8" r=".3"/>
<circle cx="192.3" cy="132.2" r=".3"/>
<circle cx="192.3" cy="131.5" r=".3"/>
<circle cx="194.9" cy="129.2" r=".3"/>
<circle cx="195" cy="127.9" r=".3"/>
<circle cx="195.1" cy="128.6" r=".3"/>
<circle cx="195.6" cy="129.2" r=".3"/>
<circle cx="195.7" cy="128.6" r=".3"/>
<circle cx="196.3" cy="129.2" r=".3"/>
<circle cx="196.4" cy="128.6" r=".3"/>
<circle cx="198.9" cy="127.7" r=".3"/>
<circle cx="198.9" cy="126.3" r=".3"/>
<circle cx="198.9" cy="127" r=".3"/>
<circle cx="199.4" cy="123" r=".3"/>
<circle cx="199.5" cy="127.4" r=".3"/>
<circle cx="199.5" cy="126.7" r=".3"/>
<circle cx="200.3" cy="121.1" r=".3"/>
<circle cx="200.6" cy="124.3" r=".3"/>
<circle cx="200.9" cy="137.7" r=".35"/>
<circle cx="201.4" cy="138.9" r=".35"/>
<circle cx="201.4" cy="136.6" r=".35"/>
<circle cx="201.6" cy="124.4" r=".3"/>
<circle cx="202.2" cy="125" r=".3"/>
<circle cx="202.5" cy="132.1" r=".3"/>
<circle cx="202.5" cy="137.7" r="2.2"/>
<circle cx="202.5" cy="136.1" r=".35"/>
<circle cx="202.5" cy="139.4" r=".35"/>
<circle cx="202.9" cy="120.2" r=".3"/>
<circle cx="203" cy="123.6" r=".3"/>
<circle cx="203" cy="125.9" r=".3"/>
<circle cx="203.7" cy="138.9" r=".35"/>
<circle cx="203.7" cy="136.6" r=".35"/>
<circle cx="204" cy="120.8" r=".3"/>
<circle cx="204.2" cy="137.7" r=".35"/>
<circle cx="205.3" cy="120.8" r=".3"/>
<circle cx="206.3" cy="126.7" r=".3"/>
<circle cx="207.6" cy="134.3" r=".3"/>
<circle cx="208.3" cy="131" r=".3"/>
<circle cx="208.5" cy="135.3" r=".3"/>
<circle cx="208.6" cy="128.8" r=".3"/>
<circle cx="208.9" cy="133.3" r=".3"/>
<circle cx="209.3" cy="131.9" r=".3"/>
<circle cx="209.5" cy="122.4" r=".3"/>
<circle cx="209.8" cy="138" r=".3"/>
<circle cx="209.8" cy="137.1" r=".3"/>
<circle cx="212.5" cy="123" r=".3"/>
<circle cx="212.8" cy="139.6" r=".3"/>
<circle cx="214.1" cy="121.2" r=".76"/>
<circle cx="215.7" cy="138.7" r=".3"/>
<circle cx="216.6" cy="123.8" r=".3"/>
<circle cx="217" cy="138.8" r=".3"/>
<circle cx="217.1" cy="121.2" r=".76"/>
<circle cx="220.1" cy="121.2" r=".76"/>
<circle cx="221.2" cy="139.1" r=".3"/>
<circle cx="221.8" cy="127.7" r=".3"/>
<circle cx="221.8" cy="136.5" r=".3"/>
<circle cx="221.9" cy="126.8" r=".3"/>
<circle cx="222" cy="138.2" r=".3"/>
<circle cx="222.5" cy="133" r=".3"/>
<circle cx="222.6" cy="131.5" r=".3"/>
<circle cx="222.7" cy="129.2" r=".3"/>
<circle cx="222.7" cy="134.7" r=".3"/>
<circle cx="226.5" cy="139.3" r=".3"/>
<circle cx="226.5" cy="135.5" r=".65"/>
<circle cx="226.5" cy="130.4" r=".65"/>
<circle cx="226.5" cy="133" r=".65"/>
<circle cx="227.5" cy="127.5" r=".3"/>
<circle cx="228.3" cy="126.3" r=".3"/>
<circle cx="230.4" cy="131.3" r=".4"/>
<circle cx="230.9" cy="126.7" r=".3"/>
<circle cx="231.1" cy="127.8" r=".3"/>
<circle cx="233" cy="128.4" r=".3"/>
<circle cx="235" cy="127.2" r=".3"/>
<circle cx="236" cy="128.1" r=".3"/>
</g>
<path d="M151.3 75.2h.6M156.8 75.2h.6M156.8 79.4h.6M227.4 75.2h.6M232.9 75.2h.6M232.9 79.4h.6M89.7 130.1h.6M89.7 125.9h.6M95.2 130.1h.6M165 131.1h.6M165 126.9h.6M170.5 131.1h.6" fill="none" stroke="#000" stroke-width="2.7"/>
<path d="M114.8 89.1h.7M117.4 91.2h1.1M120.4 89.1h.7M190.8 89h.7M193.4 91.2h1.1M196.4 89h.7M126.1 117.3h.7M128.7 115.1h1.1M131.7 117.3h.7M201.3 117.3h.7M203.9 115.2h1.1M206.9 117.3h.7" fill="none" stroke="#000" stroke-width="1.1"/>
<g fill="none" stroke="#000" stroke-width=".21">
<path d="M90.1 78l-1.1 1.1h-1.6M91.2 78.1l.8 .7h2.9M91.5 79.6l.6 .6h2.1M95.9 73.4l1.6 1.6v6.9l1.2 1.1h4.4l2.2 2.2M101.7 73.2h-1.7l-.1 .2M103.8 67.7l1.2-1.2h3.3l.6 .7h4.5l1.4 1.4v3.4M105.6 67.4h-.5l-.8 .8h-3.2l-2.3 2.3v3.5l1 .9 .2-.2h1.7M106.6 67.7h5.3l.7 .7M109.2 66.6l-.4-.4h-7.5l-2.8 2.8v8.8l1.8 1.7h.2M111.1 73.2h.8l1-.9h1.1l.3 .3v6l-3 3h-9.8l-.4-.4v-2l-.5-.6M113.1 74.5l-.2 .2h-1.8M165.7 78.1l-1 1h-1.3"/>
<path d="M167.3 78l.8 .8h2.8M167.4 79.3l.8 .8h2M172 73.4l1.6 1.6v7.4l.7 .7h4.9l2.1 2.1M177.8 73.2h-1.7l-.1 .1M180.8 67.2l.2-.3 8.5 .2 1.3 1.4v3.5M181.9 67.7l-.3 .3h-4.2l-2.6 2.5v3.4l1 1 .2-.2h1.8M183.7 67.5h4.1l.9 .9M185.2 66.6l-.4-.5h-7.4l-2.9 2.9v8.7l1.8 1.8h.2M187.2 73.2h.8l.7-.7v-.5l.3-.3h.5l1.6 1.6v5.6l-1.7 1.7h-1.6l-1.2 1.2h-8.8l-.7-.6v-2.1l-.5-.5M189.2 74.5l-.3 .2h-1.7M103 83.9v.4l2.3 2.4v1.5M114 82.9v.3l.7 .7h.8l.4-.5v-.5h.3l1.6 1.6 .1 2.9-.6 .6v1.3"/>
<path d="M114 85.2v-.6l.3-.3h1.5l.1 .1v.8l.4 .3h.8M115 82.9v-.5l-.6-.6h-.7l-.6 .6v1.3l.3 .3M117.1 86.6h-.8l-.4 .4 .7 .7v1.6M118.4 85.6v1.6l.4 .4-.9 .9v.8M119.1 81.1h.1M119.3 80.5l-.2 .2h-6.5l-1.8 1.8h-3.1M119.6 81.1h.1M120.2 81.4l-.3-.3h-7.1l-2.4 2.3h-3.2l-.8-.8-.6 .1M120.8 82l-.2-.2-.1 .1h-1l-.5-.5h-6.1l-2.4 2.4h-3.8M126.6 88.9l-.9-.8h-.9l-5.5 5.5v.3M126.9 87.6l-.2-.2h-3.9l-.8 .8M127.2 88.5h-.3l-.7-.7h-1.5l-6.3 6.2v.3"/>
<path d="M154.7 92.8v.6l-2.5 2.5M157.4 97.4l-2 2h-2.9M160 89.5l-2.6 2.6v.3M190.1 82.9v-.7l.3-.3h.9l.7 .7v.3l1.7 1.7v2.9l-.4 .4v1.4M190.1 85.2v-.3l.8-.8h.3l.8 .8v.3l.3 .3h.8M191 82.9v.6l-.4 .4h-1.7M193.1 86.6h-.7l-.4 .4 .7 .6v1.7M194.3 85v2.3l.2 .2-.5 .6v1.2M195.4 80.5l-.5 .5h-7l-1.2 1.2h-2.6l-1 1v3.9l1.2 1.1M196.3 81.3h-8.3l-1.9 1.9h-.3M196.8 81.9l-.1-.2-.2 .2h-.9l-.3-.3h-6.6l-.4 .4v6.6l-.7 .7h-8.2l-1.1-1.1M202.4 88.6h-1.2l-2 2v.5"/>
<path d="M202.9 87.4h-3.9l-.9 .8M203.2 88.5l-.5-.5h-2.5l-5.7 5.7M217 86.4h4.4l4.1 4.1v5.7M230.8 93.1h-2.5l-2.3 2.2v3.5l-.3 .3M233.3 93.1h2l1.2 1.2M233.4 98l-1.8 1.7h-1.4M88.6 114l2.2 2.2h19.7l6.1 6.1h.2M88.6 109l2.5-2.5h10.5l15 15h.3M91.1 109v1.1l2 2h6.4l.6 .6v.4M93.7 114h1.2l.4 .5M93.7 109v.8l1.3 1.4h2.3M97.4 113.7v2l-.2 .2h-4.2l-1.9-1.9"/>
<path d="M102.8 105.8h.2l12.5 12.6h2l.3-.3v-1.4l-.6-.6M107.5 105.1l-.6 .7v2.5M116.6 112.7l.7-.7h11.3l2 2-.1 4.7 .7 .6-.4 .4h-.7M120 112.8h-2l-1.6 1.6v2.6l.8 .8M122.9 112.6l.3 .3h4.6M124 111.1l7.8-.1 5 5h9.1M129.2 117v1.1l-.7 .7 .3 .2v1.7M129.9 117v1.4l-.4 .4v2.9l1.7 1.7v.3l.7 .7h.9l.3-.3v-.7M138.9 118.1l1.4 1.4v3.2l-.3 .3h-1.4l-1.4 1.4h-1l-1.4 1.4h-7M144.9 118.1l-1.4-1.5h-6.3l-2.1 2.1v5.4l-.9 .9h-6l-.6-.6h-.9l-.2 .2-.1-.2M145.9 116h.1M146.4 115.5l-.5 .5"/>
<path d="M163.8 114.1l2.2 2.2h19.8l6 6h.2v.3M163.8 109h.3l1.1 1.1M166.4 109v1.1l2 2h6.3l.6 .6v.4M168.9 114.1h1.2l.5 .5M168.9 109v.9l1.3 1.3h2.3M172.6 113.7v2l-.2 .2h-4.2l-1.8-1.8M180.5 111h.8l10.7 10.8M184.4 109.5h2.2l1-1h4.1v.8l1 1.1M188.6 109.5l.8 .8v6.9l1.2 1.2h2.2l.2-.2v-1.4l-.4-.4M191.9 112.7l.7-.6h11.2l2 2v4.6l.7 .7-.4 .4h-.8M195.2 112.8h-1.9l-1.7 1.7v2.6l.8 .7M198.1 112.6l.4 .4h4.5"/>
<path d="M204.5 117.1v1l-.8 .7 .3 .3v1.7M205.1 117.1v1.3l-.4 .5v2.8l1.7 1.8v.3l.7 .6h1l.2-.3v-.6M214.1 118.2l1.6 1.5v2.2l-2.8 2.7h-1.5l-1.2 1.3h-7.2M220.1 118.2l-1.5-1.5h-7.1l-1.4 1.4v6.3l-.6 .6h-6.1l-.5-.5h-1l-.1 .1-.2-.2M127.6 125.3h.1M130.1 120.8h.8l.3 .3v.3l.8 .8h.4l.7-.8v-.3M132.4 134.3v3.5l1.4 1.4h4.5l.6 .6h3.1l.8-.8M134.3 122.4h-1.7l-.4 .4v.6M134.5 137.9l.7 .7h5.3M136.1 131.6h-1.8l-.3 .2M137.1 123.2l-2.3 2.2h-6.6l-.9-.1-.4-.3M141.9 121.1l2 1.9h4.3l1.5 1.5v6.8l1.6 1.6"/>
<path d="M145.5 131.6h1.7l.2-.2 1 1v4.4l-2.2 2.2h-2.6l-.5-.5h-1.1l-.4 .4M146.6 127.7l-.5-.5v-2.1l-.2-.2h-9.4l-3.6 3.6v3.6l1 1h2.2M146.7 126.8h.2l1.8 1.8v8.7l-2.8 2.8h-7.5l-.4-.4M147.3 133l-.2 .1h-1.6M152.3 127.5h1.5l1 1M152.6 126.7h3.2l.2 .2M159.8 127.2h-1.4l-1.3 1.3M205.3 120.8h.8l.3 .4v.3l.8 .7h.4l.7-.7v-.3M207.6 134.3v3.5l1.2 1.2h4.8l.4 .4h6.9l.3-.3M209.5 122.4h-1.6l-.5 .5v.6M209.8 138l.7 .7h5.2M211.3 131.7h-1.8l-.2 .2"/>
<path d="M211.5 123.9h.1M212.5 123l-2.5 2.4h-6.6l-.9-.1-.3-.3M220.7 131.7h1.7l.2-.2 1 .9v3.5l-3 3-3.6-.1M221.8 127.7l-.5-.5v-2l-.2-.2h-9.3l-4.1 4v4.5l1.2 1.2h.5l.3-.4v-.4l.8-.7h.8M221.9 126.8l2 2v8.6l-2.4 2.4h-7.9l-.2-.2h-.6M222.5 133l-.2 .2h-1.6M227.5 127.5h3.4l.2 .3M228.3 126.3h2.2l.4 .4M235 127.2h-.9l-1.1 1.2"/>
</g>
<g fill="none" stroke="#000" stroke-width=".25">
<path d="M112.6 68.4h.1M112.6 68.4l.9 .9v.9l-1.3 1.3h-.6l-.5 .2M188.7 68.4l.8 .8v1l-1.2 1.2h-.7l-.4 .3M195.9 74.3l-.1 .1v5.5l2.1 2.1M121.8 82.1l-2.1-2.1v-5.7l-.3-.4 5.5-5.4h10l5.1 5.1v11.1l2.6 2.6h4.2l2.9 2.9v5.7M121.8 82.1h.1M197.9 82v.1M91.4 111.5h-3.7l-.6 .6v3.5l1.6 1.6h16.5l2.8 2.8v6l5 4.9v3.4l2.2 2.3h7.6l3-3h1.7l-.1-7.2-2.1-2.1M98.7 114h.3l1.3 1.3M166.6 111.5h-3.7l-.6 .6v3.5l1.6 1.6h16.6l2.7 2.8v6l4.7 4.6v3l3 3h7.1l4.7-4.6v-5.6l-2.1-2.1M174 114.1h.2l1.3 1.3M125.3 124.2v.1"/>
<path d="M134.5 137.9h.1M136.1 134.6l-.5 .3h-.7l-1.2 1.2v1l.8 .8M200.6 124.3h.1M211.3 134.7l-.5 .2h-.6l-1.3 1.3v.9l.9 .9M217.1 121.2l2.3 2.2h4.1l.8 .8v6.6l2.2 2.2"/>
</g>
</svg>
